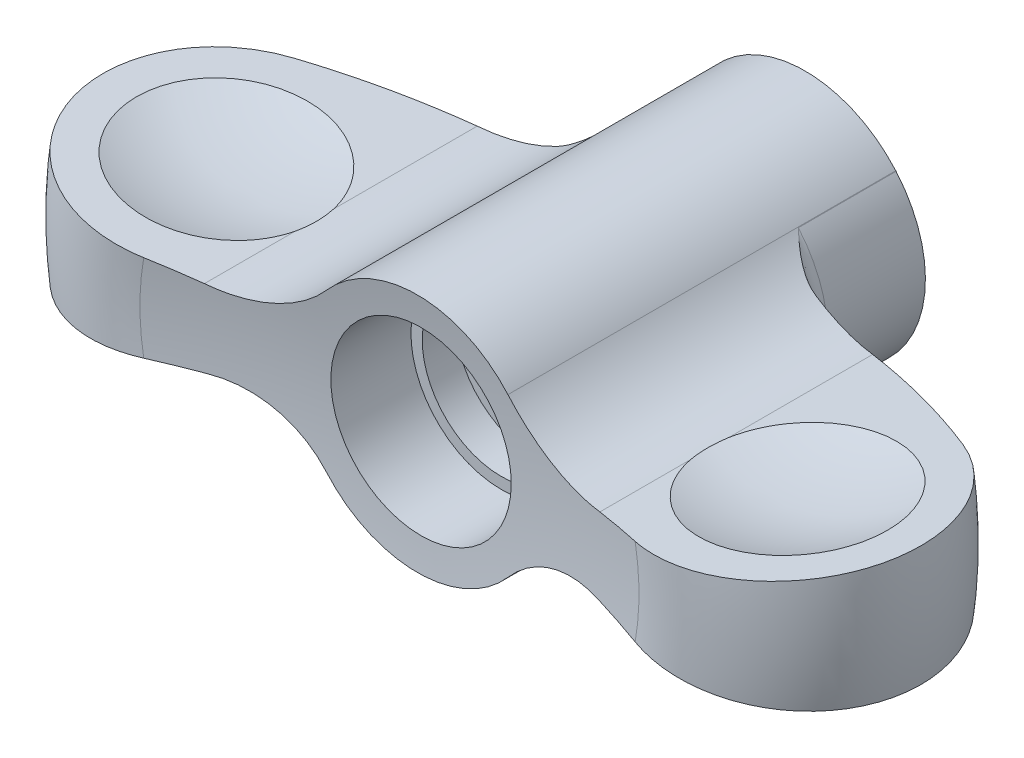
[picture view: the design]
ISO-10303-21;
HEADER;
FILE_DESCRIPTION(('STEP AP214'),'2;1');
FILE_NAME('part.step','',(''),(''),'','','');
FILE_SCHEMA(('AUTOMOTIVE_DESIGN { 1 0 10303 214 1 1 1 1 }'));
ENDSEC;
DATA;
#1=APPLICATION_CONTEXT('core data for automotive mechanical design processes');
#2=APPLICATION_PROTOCOL_DEFINITION('international standard','automotive_design',2000,#1);
#3=PRODUCT_CONTEXT('',#1,'mechanical');
#4=PRODUCT('Part','Part','',(#3));
#5=PRODUCT_RELATED_PRODUCT_CATEGORY('part','',(#4));
#6=PRODUCT_DEFINITION_FORMATION('','',#4);
#7=PRODUCT_DEFINITION_CONTEXT('part definition',#1,'design');
#8=PRODUCT_DEFINITION('design','',#6,#7);
#9=PRODUCT_DEFINITION_SHAPE('','',#8);
#10=(LENGTH_UNIT() NAMED_UNIT(*) SI_UNIT(.MILLI.,.METRE.));
#11=(NAMED_UNIT(*) PLANE_ANGLE_UNIT() SI_UNIT($,.RADIAN.));
#12=(NAMED_UNIT(*) SI_UNIT($,.STERADIAN.) SOLID_ANGLE_UNIT());
#13=UNCERTAINTY_MEASURE_WITH_UNIT(LENGTH_MEASURE(1.E-05),#10,'distance_accuracy_value','');
#14=(GEOMETRIC_REPRESENTATION_CONTEXT(3) GLOBAL_UNCERTAINTY_ASSIGNED_CONTEXT((#13)) GLOBAL_UNIT_ASSIGNED_CONTEXT((#10,
#11,#12)) REPRESENTATION_CONTEXT('',''));
#15=CARTESIAN_POINT('',(0.,0.,0.));
#16=DIRECTION('',(0.,0.,1.));
#17=DIRECTION('',(1.,0.,0.));
#18=AXIS2_PLACEMENT_3D('',#15,#16,#17);
#19=CARTESIAN_POINT('',(0.,0.,6.5));
#20=DIRECTION('',(0.,0.,1.));
#21=DIRECTION('',(0.,-1.,0.));
#22=AXIS2_PLACEMENT_3D('',#19,#20,#21);
#23=TOROIDAL_SURFACE('',#22,9.4,1.40000000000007);
#24=DIRECTION('',(0.,0.,1.));
#25=VECTOR('',#24,1.);
#26=CARTESIAN_POINT('',(6.03890778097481,-5.2470556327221,-7.0380739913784));
#27=LINE('',#26,#25);
#28=CARTESIAN_POINT('',(6.03890778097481,-5.2470556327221,6.5));
#29=VERTEX_POINT('',#28);
#30=CARTESIAN_POINT('',(6.03890778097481,-5.2470556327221,6.50212008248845));
#31=VERTEX_POINT('',#30);
#32=EDGE_CURVE('E180',#29,#31,#27,.T.);
#33=ORIENTED_EDGE('',*,*,#32,.F.);
#34=CARTESIAN_POINT('',(0.,0.,6.5));
#35=DIRECTION('',(0.,0.,1.));
#36=DIRECTION('',(0.,-1.,0.));
#37=AXIS2_PLACEMENT_3D('',#34,#35,#36);
#38=CIRCLE('',#37,8.);
#39=CARTESIAN_POINT('',(6.0470062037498,5.23772049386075,6.5));
#40=VERTEX_POINT('',#39);
#41=EDGE_CURVE('E402',#29,#40,#38,.T.);
#42=ORIENTED_EDGE('',*,*,#41,.T.);
#43=CARTESIAN_POINT('',(8.59898254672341,3.29412567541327,7.8868206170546));
#44=CARTESIAN_POINT('',(8.51141815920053,3.33631021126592,7.87757295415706));
#45=CARTESIAN_POINT('',(8.42512324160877,3.37986689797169,7.86383925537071));
#46=CARTESIAN_POINT('',(8.25552733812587,3.46930142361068,7.82879311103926));
#47=CARTESIAN_POINT('',(8.17222071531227,3.51517445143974,7.80749586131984));
#48=CARTESIAN_POINT('',(8.00928400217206,3.60865711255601,7.75884124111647));
#49=CARTESIAN_POINT('',(7.92963203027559,3.65625212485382,7.73152791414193));
#50=CARTESIAN_POINT('',(7.77338079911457,3.75327693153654,7.67180748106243));
#51=CARTESIAN_POINT('',(7.69678296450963,3.80270756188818,7.63939803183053));
#52=CARTESIAN_POINT('',(7.51724415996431,3.9228836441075,7.55691032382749));
#53=CARTESIAN_POINT('',(7.41571994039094,3.99440279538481,7.50487985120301));
#54=CARTESIAN_POINT('',(7.21816387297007,4.14040328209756,7.39471306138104));
#55=CARTESIAN_POINT('',(7.12213718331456,4.21488729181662,7.3365711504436));
#56=CARTESIAN_POINT('',(6.89909833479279,4.39600037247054,7.19247655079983));
#57=CARTESIAN_POINT('',(6.77446584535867,4.50392052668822,7.10446467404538));
#58=CARTESIAN_POINT('',(6.57485157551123,4.68763024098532,6.9540735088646));
#59=CARTESIAN_POINT('',(6.49736321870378,4.7619072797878,6.89312126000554));
#60=CARTESIAN_POINT('',(6.37296054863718,4.88601102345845,6.79178977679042));
#61=CARTESIAN_POINT('',(6.32499252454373,4.93511681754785,6.75182074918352));
#62=CARTESIAN_POINT('',(6.24779625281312,5.01619850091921,6.68620361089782));
#63=CARTESIAN_POINT('',(6.21813895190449,5.04786120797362,6.66067187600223));
#64=CARTESIAN_POINT('',(6.17033482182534,5.09973563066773,6.61900123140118));
#65=CARTESIAN_POINT('',(6.15201397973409,5.11982116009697,6.60290481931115));
#66=CARTESIAN_POINT('',(6.12244478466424,5.15257170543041,6.57667362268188));
#67=CARTESIAN_POINT('',(6.11112210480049,5.16519318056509,6.56656814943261));
#68=CARTESIAN_POINT('',(6.09283224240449,5.18571154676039,6.55006512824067));
#69=CARTESIAN_POINT('',(6.08582724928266,5.19360153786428,6.54370123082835));
#70=CARTESIAN_POINT('',(6.07451533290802,5.2063931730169,6.53324372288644));
#71=CARTESIAN_POINT('',(6.07018138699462,5.21130628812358,6.52919336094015));
#72=CARTESIAN_POINT('',(6.06319526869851,5.21924541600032,6.52245610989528));
#73=CARTESIAN_POINT('',(6.06051754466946,5.22229316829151,6.51982285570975));
#74=CARTESIAN_POINT('',(6.05622209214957,5.22718951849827,6.51535418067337));
#75=CARTESIAN_POINT('',(6.05457550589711,5.22906827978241,6.51357999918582));
#76=CARTESIAN_POINT('',(6.05195439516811,5.23206168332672,6.51048008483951));
#77=CARTESIAN_POINT('',(6.05094876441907,5.23321085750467,6.50921868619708));
#78=CARTESIAN_POINT('',(6.04953567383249,5.23482648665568,6.50715333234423));
#79=CARTESIAN_POINT('',(6.04907752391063,5.2353504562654,6.50643002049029));
#80=CARTESIAN_POINT('',(6.04823578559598,5.2363133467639,6.50488896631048));
#81=CARTESIAN_POINT('',(6.04785159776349,5.2367529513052,6.50407207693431));
#82=CARTESIAN_POINT('',(6.04743690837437,5.23722752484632,6.50283591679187));
#83=CARTESIAN_POINT('',(6.04733310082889,5.23734633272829,6.50247536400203));
#84=CARTESIAN_POINT('',(6.04716429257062,5.23753954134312,6.50173449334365));
#85=CARTESIAN_POINT('',(6.04709913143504,5.23761412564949,6.50135426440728));
#86=CARTESIAN_POINT('',(6.04703741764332,5.23768476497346,6.50077580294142));
#87=CARTESIAN_POINT('',(6.04702284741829,5.23770144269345,6.50058184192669));
#88=CARTESIAN_POINT('',(6.04700611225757,5.23772059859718,6.50019185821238));
#89=CARTESIAN_POINT('',(6.04700400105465,5.23772301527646,6.49999583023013));
#90=CARTESIAN_POINT('',(6.0470084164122,5.23771796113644,6.4997999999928));
#91=B_SPLINE_CURVE_WITH_KNOTS('',3,(#43,#44,#45,#46,#47,#48,#49,#50,#51,#52,#53,#54,#55,#56,#57,
#58,#59,#60,#61,#62,#63,#64,#65,#66,#67,#68,#69,#70,#71,#72,#73,#74,#75,#76,#77,#78,#79,#80,#81,
#82,#83,#84,#85,#86,#87,#88,#89,#90),.UNSPECIFIED.,.F.,.F.,(4,2,2,2,2,2,2,2,2,2,2,2,2,2,2,2,2,2,
2,2,2,2,2,4),(0.,0.292609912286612,0.58463524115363,0.874589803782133,1.16467807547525,
1.56824756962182,1.97218971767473,2.53235699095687,2.9025934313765,3.14087410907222,
3.29188442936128,3.38666478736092,3.44588137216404,3.48284532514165,3.50595247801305,
3.52045898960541,3.52964962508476,3.53557823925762,3.53858720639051,3.54157065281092,
3.54274772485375,3.54391987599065,3.54450469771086,3.54509203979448),.UNSPECIFIED.);
#92=CARTESIAN_POINT('',(8.59708881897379,3.29503849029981,7.8866206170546));
#93=VERTEX_POINT('',#92);
#94=EDGE_CURVE('E347',#93,#40,#91,.T.);
#95=ORIENTED_EDGE('',*,*,#94,.F.);
#96=CARTESIAN_POINT('',(0.,0.,7.8866206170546));
#97=DIRECTION('',(0.,0.,1.));
#98=DIRECTION('',(0.,-1.,0.));
#99=AXIS2_PLACEMENT_3D('',#96,#97,#98);
#100=CIRCLE('',#99,9.20691125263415);
#101=CARTESIAN_POINT('',(8.59734587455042,-3.29436772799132,7.8866206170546));
#102=VERTEX_POINT('',#101);
#103=EDGE_CURVE('E398',#102,#93,#100,.T.);
#104=ORIENTED_EDGE('',*,*,#103,.F.);
#105=CARTESIAN_POINT('',(9.24838774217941,-3.01522896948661,7.8611549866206));
#106=CARTESIAN_POINT('',(9.19367387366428,-3.03586597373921,7.87212843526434));
#107=CARTESIAN_POINT('',(9.13880326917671,-3.05725699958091,7.88061358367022));
#108=CARTESIAN_POINT('',(9.02918340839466,-3.10140121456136,7.89300588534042));
#109=CARTESIAN_POINT('',(8.97443409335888,-3.12415231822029,7.8969198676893));
#110=CARTESIAN_POINT('',(8.81189994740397,-3.19383993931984,7.90240025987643));
#111=CARTESIAN_POINT('',(8.70468460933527,-3.24264189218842,7.8979138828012));
#112=CARTESIAN_POINT('',(8.51244986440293,-3.33527790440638,7.87768998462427));
#113=CARTESIAN_POINT('',(8.42685948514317,-3.37846333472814,7.86408345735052));
#114=CARTESIAN_POINT('',(8.25844994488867,-3.46721413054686,7.82939829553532));
#115=CARTESIAN_POINT('',(8.1756320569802,-3.51278056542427,7.80831627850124));
#116=CARTESIAN_POINT('',(7.93073591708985,-3.65314361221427,7.73552099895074));
#117=CARTESIAN_POINT('',(7.77324575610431,-3.75110326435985,7.67439750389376));
#118=CARTESIAN_POINT('',(7.51464053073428,-3.92422259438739,7.55555975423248));
#119=CARTESIAN_POINT('',(7.41040744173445,-3.99776965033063,7.50198430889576));
#120=CARTESIAN_POINT('',(7.20775000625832,-4.14796966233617,7.38844495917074));
#121=CARTESIAN_POINT('',(7.10932762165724,-4.2246236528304,7.32847891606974));
#122=CARTESIAN_POINT('',(6.91810375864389,-4.3807228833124,7.20404785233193));
#123=CARTESIAN_POINT('',(6.82529242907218,-4.46016282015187,7.13959117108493));
#124=CARTESIAN_POINT('',(6.64465512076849,-4.62196874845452,7.0075093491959));
#125=CARTESIAN_POINT('',(6.55682825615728,-4.70433421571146,6.93988477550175));
#126=CARTESIAN_POINT('',(6.43396887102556,-4.82482237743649,6.84137296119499));
#127=CARTESIAN_POINT('',(6.3970838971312,-4.86171240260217,6.81126516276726));
#128=CARTESIAN_POINT('',(6.32415661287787,-4.93608562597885,6.75076275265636));
#129=CARTESIAN_POINT('',(6.28811428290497,-4.97356881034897,6.72036814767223));
#130=CARTESIAN_POINT('',(6.23466025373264,-5.03025441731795,6.67467473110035));
#131=CARTESIAN_POINT('',(6.21694916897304,-5.04922052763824,6.65943137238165));
#132=CARTESIAN_POINT('',(6.18174487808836,-5.08728721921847,6.62885737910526));
#133=CARTESIAN_POINT('',(6.16425168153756,-5.10638780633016,6.61352674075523));
#134=CARTESIAN_POINT('',(6.12939253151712,-5.14482758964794,6.58303704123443));
#135=CARTESIAN_POINT('',(6.11202655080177,-5.16416673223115,6.56787794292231));
#136=CARTESIAN_POINT('',(6.07777325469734,-5.20267654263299,6.53681590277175));
#137=CARTESIAN_POINT('',(6.06088576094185,-5.22184727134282,6.52091324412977));
#138=CARTESIAN_POINT('',(6.04125231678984,-5.24436288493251,6.50407143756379));
#139=CARTESIAN_POINT('',(6.03883130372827,-5.24714315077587,6.50202251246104));
#140=CARTESIAN_POINT('',(6.036402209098,-5.24993655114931,6.5));
#141=B_SPLINE_CURVE_WITH_KNOTS('',3,(#105,#106,#107,#108,#109,#110,#111,#112,#113,#114,#115,
#116,#117,#118,#119,#120,#121,#122,#123,#124,#125,#126,#127,#128,#129,#130,#131,#132,#133,#134,
#135,#136,#137,#138,#139,#140),.UNSPECIFIED.,.F.,.F.,(4,2,2,2,2,2,2,2,2,2,2,2,2,2,2,2,2,4),(0.,
0.178348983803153,0.356431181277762,0.708912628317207,0.999032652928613,1.28928411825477,
1.87321137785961,2.28803676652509,2.70300142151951,3.1172150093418,3.53135474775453,
3.71204340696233,3.89272785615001,3.98301462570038,4.07330534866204,4.16357613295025,
4.25381281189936,4.26646608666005),.UNSPECIFIED.);
#142=EDGE_CURVE('E331',#31,#102,#141,.F.);
#143=ORIENTED_EDGE('',*,*,#142,.F.);
#144=EDGE_LOOP('',(#33,#42,#95,#104,#143));
#145=FACE_BOUND('',#144,.T.);
#146=ADVANCED_FACE('F14',(#145),#23,.F.);
#147=CARTESIAN_POINT('',(0.,0.,84.9218512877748));
#148=DIRECTION('',(0.,0.,1.));
#149=DIRECTION('',(0.,-1.,0.));
#150=AXIS2_PLACEMENT_3D('',#147,#148,#149);
#151=DEGENERATE_TOROIDAL_SURFACE('',#150,0.267106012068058,59.7,.F.);
#152=CARTESIAN_POINT('',(0.,0.,25.5517124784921));
#153=DIRECTION('',(0.,0.,1.));
#154=DIRECTION('',(0.,-1.,0.));
#155=AXIS2_PLACEMENT_3D('',#152,#153,#154);
#156=CIRCLE('',#155,6.);
#157=CARTESIAN_POINT('',(0.,-6.,25.5517124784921));
#158=VERTEX_POINT('',#157);
#159=EDGE_CURVE('E226',#158,#158,#156,.T.);
#160=ORIENTED_EDGE('',*,*,#159,.F.);
#161=EDGE_LOOP('',(#160));
#162=FACE_BOUND('',#161,.T.);
#163=CARTESIAN_POINT('',(12.9966083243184,-2.55402529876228,26.7711157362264));
#164=CARTESIAN_POINT('',(12.7754529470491,-2.52825709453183,26.719533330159));
#165=CARTESIAN_POINT('',(12.5528725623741,-2.5117272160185,26.6693936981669));
#166=CARTESIAN_POINT('',(12.1063783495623,-2.49733345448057,26.5723334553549));
#167=CARTESIAN_POINT('',(11.8824643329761,-2.49947227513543,26.5254133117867));
#168=CARTESIAN_POINT('',(11.4348095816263,-2.52261669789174,26.4351255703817));
#169=CARTESIAN_POINT('',(11.2110689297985,-2.54362860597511,26.3917591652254));
#170=CARTESIAN_POINT('',(10.7654590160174,-2.60455176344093,26.3089232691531));
#171=CARTESIAN_POINT('',(10.5435896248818,-2.64446169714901,26.2694535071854));
#172=CARTESIAN_POINT('',(10.1029278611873,-2.7431637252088,26.1946447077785));
#173=CARTESIAN_POINT('',(9.88414203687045,-2.80199107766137,26.1593135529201));
#174=CARTESIAN_POINT('',(9.45174044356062,-2.93823754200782,26.0931563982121));
#175=CARTESIAN_POINT('',(9.23812452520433,-3.01565611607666,26.0623302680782));
#176=CARTESIAN_POINT('',(8.81794496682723,-3.18856082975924,26.0054747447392));
#177=CARTESIAN_POINT('',(8.61137399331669,-3.28402745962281,25.979440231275));
#178=CARTESIAN_POINT('',(8.20669244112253,-3.49247951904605,25.9323600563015));
#179=CARTESIAN_POINT('',(8.00858079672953,-3.60546273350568,25.9113137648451));
#180=CARTESIAN_POINT('',(7.65039872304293,-3.83057518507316,25.8770779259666));
#181=CARTESIAN_POINT('',(7.48897596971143,-3.94045548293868,25.8631917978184));
#182=CARTESIAN_POINT('',(7.1744293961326,-4.17187167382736,25.8393036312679));
#183=CARTESIAN_POINT('',(7.02130457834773,-4.29340616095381,25.8293011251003));
#184=CARTESIAN_POINT('',(6.72399395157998,-4.54769946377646,25.8132388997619));
#185=CARTESIAN_POINT('',(6.57982418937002,-4.68047747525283,25.8071860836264));
#186=CARTESIAN_POINT('',(6.30152732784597,-4.95633540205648,25.7990887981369));
#187=CARTESIAN_POINT('',(6.16740216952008,-5.09941729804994,25.7970451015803));
#188=CARTESIAN_POINT('',(6.03873367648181,-5.2472556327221,25.7970260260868));
#189=B_SPLINE_CURVE_WITH_KNOTS('',3,(#163,#164,#165,#166,#167,#168,#169,#170,#171,#172,#173,
#174,#175,#176,#177,#178,#179,#180,#181,#182,#183,#184,#185,#186,#187,#188),.UNSPECIFIED.,.F.,
.F.,(4,2,2,2,2,2,2,2,2,2,2,2,4),(0.,0.685469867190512,1.37103900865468,2.05683730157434,
2.74258785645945,3.42962398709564,4.1166402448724,4.80291804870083,5.48910913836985,
6.07586072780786,6.66254162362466,7.25024515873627,7.83806196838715),.UNSPECIFIED.);
#190=CARTESIAN_POINT('',(12.9964083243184,-2.55400201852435,26.7710690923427));
#191=VERTEX_POINT('',#190);
#192=CARTESIAN_POINT('',(6.03890778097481,-5.2470556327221,25.7970260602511));
#193=VERTEX_POINT('',#192);
#194=EDGE_CURVE('E337',#191,#193,#189,.T.);
#195=ORIENTED_EDGE('',*,*,#194,.F.);
#196=CARTESIAN_POINT('',(12.9962083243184,-2.55398166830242,26.7710225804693));
#197=CARTESIAN_POINT('',(13.5586098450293,-2.61120664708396,26.9018172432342));
#198=CARTESIAN_POINT('',(14.1188767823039,-2.66821442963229,27.0407918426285));
#199=CARTESIAN_POINT('',(15.2351414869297,-2.78179560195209,27.3351009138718));
#200=CARTESIAN_POINT('',(15.7911392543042,-2.83836899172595,27.4904353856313));
#201=CARTESIAN_POINT('',(16.3450024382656,-2.89472518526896,27.6539497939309));
#202=B_SPLINE_CURVE_WITH_KNOTS('',3,(#196,#197,#198,#199,#200,#201),.UNSPECIFIED.,.F.,.F.,(4,2,
4),(0.,1.74016258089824,3.48032515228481),.UNSPECIFIED.);
#203=CARTESIAN_POINT('',(16.3443249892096,-2.89465625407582,27.6537497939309));
#204=VERTEX_POINT('',#203);
#205=EDGE_CURVE('E277',#191,#204,#202,.T.);
#206=ORIENTED_EDGE('',*,*,#205,.T.);
#207=CARTESIAN_POINT('',(0.,0.,27.6537497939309));
#208=DIRECTION('',(0.,0.,1.));
#209=DIRECTION('',(0.,-1.,0.));
#210=AXIS2_PLACEMENT_3D('',#207,#208,#209);
#211=CIRCLE('',#210,16.5986744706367);
#212=CARTESIAN_POINT('',(16.3437132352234,2.89810832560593,27.6537497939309));
#213=VERTEX_POINT('',#212);
#214=EDGE_CURVE('E390',#204,#213,#211,.T.);
#215=ORIENTED_EDGE('',*,*,#214,.T.);
#216=CARTESIAN_POINT('',(13.1526156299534,2.57444288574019,26.8078255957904));
#217=CARTESIAN_POINT('',(13.6884788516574,2.6287942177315,26.9339805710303));
#218=CARTESIAN_POINT('',(14.2223917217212,2.68294773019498,27.0675684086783));
#219=CARTESIAN_POINT('',(15.2863167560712,2.79085911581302,27.3496098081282));
#220=CARTESIAN_POINT('',(15.8163289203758,2.84461698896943,27.4980633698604));
#221=CARTESIAN_POINT('',(16.3443907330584,2.89817704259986,27.6539497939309));
#222=B_SPLINE_CURVE_WITH_KNOTS('',3,(#216,#217,#218,#219,#220,#221),.UNSPECIFIED.,.F.,.F.,(4,2,
4),(0.,1.65908751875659,3.31817502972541),.UNSPECIFIED.);
#223=CARTESIAN_POINT('',(13.1528156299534,2.57446317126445,26.8078726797));
#224=VERTEX_POINT('',#223);
#225=EDGE_CURVE('E296',#224,#213,#222,.T.);
#226=ORIENTED_EDGE('',*,*,#225,.F.);
#227=CARTESIAN_POINT('',(6.024532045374,5.26355694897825,25.7970262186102));
#228=CARTESIAN_POINT('',(6.16690476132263,5.09913304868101,25.7968869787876));
#229=CARTESIAN_POINT('',(6.31601972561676,4.94055485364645,25.7992439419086));
#230=CARTESIAN_POINT('',(6.62655584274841,4.63614521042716,25.8088925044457));
#231=CARTESIAN_POINT('',(6.7879754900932,4.49031220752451,25.8161835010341));
#232=CARTESIAN_POINT('',(7.12145474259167,4.21284299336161,25.8356118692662));
#233=CARTESIAN_POINT('',(7.29347942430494,4.08116373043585,25.847733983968));
#234=CARTESIAN_POINT('',(7.64736462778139,3.83234945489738,25.8767149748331));
#235=CARTESIAN_POINT('',(7.82922517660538,3.71521448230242,25.893573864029));
#236=CARTESIAN_POINT('',(8.20178776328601,3.49604471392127,25.9319185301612));
#237=CARTESIAN_POINT('',(8.39250457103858,3.39403642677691,25.9534122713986));
#238=CARTESIAN_POINT('',(8.78119845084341,3.20593098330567,26.0008427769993));
#239=CARTESIAN_POINT('',(8.97917867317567,3.11984083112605,26.0267814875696));
#240=CARTESIAN_POINT('',(9.38110362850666,2.96402714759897,26.0829169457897));
#241=CARTESIAN_POINT('',(9.58505370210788,2.89431880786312,26.1131176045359));
#242=CARTESIAN_POINT('',(9.99723627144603,2.77173272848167,26.1775161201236));
#243=CARTESIAN_POINT('',(10.2054670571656,2.71884840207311,26.2117124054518));
#244=CARTESIAN_POINT('',(10.641032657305,2.62666034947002,26.286643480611));
#245=CARTESIAN_POINT('',(10.8686042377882,2.58871528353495,26.3276789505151));
#246=CARTESIAN_POINT('',(11.325443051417,2.5326356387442,26.4137825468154));
#247=CARTESIAN_POINT('',(11.5547105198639,2.51450386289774,26.4588512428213));
#248=CARTESIAN_POINT('',(12.0133084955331,2.49800092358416,26.552689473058));
#249=CARTESIAN_POINT('',(12.242638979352,2.49963935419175,26.6014607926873));
#250=CARTESIAN_POINT('',(12.6995448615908,2.5224660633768,26.7023049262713));
#251=CARTESIAN_POINT('',(12.927120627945,2.54365012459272,26.7543770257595));
#252=CARTESIAN_POINT('',(13.1530156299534,2.5744904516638,26.8079200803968));
#253=B_SPLINE_CURVE_WITH_KNOTS('',3,(#227,#228,#229,#230,#231,#232,#233,#234,#235,#236,#237,
#238,#239,#240,#241,#242,#243,#244,#245,#246,#247,#248,#249,#250,#251,#252),.UNSPECIFIED.,.F.,
.F.,(4,2,2,2,2,2,2,2,2,2,2,2,4),(0.,0.65228767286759,1.3044956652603,1.95466006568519,
2.60482625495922,3.25611868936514,3.90769702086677,4.55987722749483,5.21180178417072,
5.91390661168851,6.61611075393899,7.31865567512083,8.02104904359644),.UNSPECIFIED.);
#254=CARTESIAN_POINT('',(6.02470527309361,5.26335694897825,25.7970260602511));
#255=VERTEX_POINT('',#254);
#256=EDGE_CURVE('E375',#255,#224,#253,.T.);
#257=ORIENTED_EDGE('',*,*,#256,.F.);
#258=CARTESIAN_POINT('',(0.,0.,25.7970260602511));
#259=DIRECTION('',(0.,0.,1.));
#260=DIRECTION('',(0.,-1.,0.));
#261=AXIS2_PLACEMENT_3D('',#258,#259,#260);
#262=CIRCLE('',#261,8.);
#263=CARTESIAN_POINT('',(-6.0247052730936,5.26335694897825,25.7970260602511));
#264=VERTEX_POINT('',#263);
#265=EDGE_CURVE('E382',#255,#264,#262,.T.);
#266=ORIENTED_EDGE('',*,*,#265,.T.);
#267=CARTESIAN_POINT('',(-6.02453204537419,5.26355694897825,25.7970262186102));
#268=CARTESIAN_POINT('',(-6.16690476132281,5.099133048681,25.7968869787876));
#269=CARTESIAN_POINT('',(-6.31601972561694,4.94055485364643,25.7992439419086));
#270=CARTESIAN_POINT('',(-6.62655584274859,4.63614521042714,25.8088925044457));
#271=CARTESIAN_POINT('',(-6.78797549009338,4.4903122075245,25.8161835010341));
#272=CARTESIAN_POINT('',(-7.12145474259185,4.21284299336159,25.8356118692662));
#273=CARTESIAN_POINT('',(-7.29347942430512,4.08116373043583,25.847733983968));
#274=CARTESIAN_POINT('',(-7.64736462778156,3.83234945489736,25.8767149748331));
#275=CARTESIAN_POINT('',(-7.82922517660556,3.71521448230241,25.893573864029));
#276=CARTESIAN_POINT('',(-8.20178776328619,3.49604471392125,25.9319185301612));
#277=CARTESIAN_POINT('',(-8.39250457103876,3.39403642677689,25.9534122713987));
#278=CARTESIAN_POINT('',(-8.78119845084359,3.20593098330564,26.0008427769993));
#279=CARTESIAN_POINT('',(-8.97917867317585,3.11984083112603,26.0267814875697));
#280=CARTESIAN_POINT('',(-9.38110362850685,2.96402714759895,26.0829169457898));
#281=CARTESIAN_POINT('',(-9.58505370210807,2.89431880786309,26.1131176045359));
#282=CARTESIAN_POINT('',(-9.99723627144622,2.77173272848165,26.1775161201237));
#283=CARTESIAN_POINT('',(-10.2054670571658,2.7188484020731,26.2117124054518));
#284=CARTESIAN_POINT('',(-10.6410326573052,2.62666034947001,26.286643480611));
#285=CARTESIAN_POINT('',(-10.8686042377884,2.58871528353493,26.3276789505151));
#286=CARTESIAN_POINT('',(-11.3254430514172,2.53263563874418,26.4137825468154));
#287=CARTESIAN_POINT('',(-11.5547105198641,2.51450386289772,26.4588512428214));
#288=CARTESIAN_POINT('',(-12.0133084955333,2.49800092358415,26.5526894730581));
#289=CARTESIAN_POINT('',(-12.2426389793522,2.49963935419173,26.6014607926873));
#290=CARTESIAN_POINT('',(-12.699544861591,2.52246606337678,26.7023049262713));
#291=CARTESIAN_POINT('',(-12.9271206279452,2.5436501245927,26.7543770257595));
#292=CARTESIAN_POINT('',(-13.1530156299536,2.57449045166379,26.8079200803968));
#293=B_SPLINE_CURVE_WITH_KNOTS('',3,(#267,#268,#269,#270,#271,#272,#273,#274,#275,#276,#277,
#278,#279,#280,#281,#282,#283,#284,#285,#286,#287,#288,#289,#290,#291,#292),.UNSPECIFIED.,.F.,
.F.,(4,2,2,2,2,2,2,2,2,2,2,2,4),(0.,0.652287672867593,1.3044956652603,1.95466006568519,
2.60482625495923,3.25611868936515,3.90769702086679,4.55987722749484,5.21180178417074,
5.91390661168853,6.61611075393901,7.31865567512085,8.02104904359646),.UNSPECIFIED.);
#294=CARTESIAN_POINT('',(-13.1528156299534,2.57446317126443,26.8078726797));
#295=VERTEX_POINT('',#294);
#296=EDGE_CURVE('E497',#264,#295,#293,.T.);
#297=ORIENTED_EDGE('',*,*,#296,.T.);
#298=CARTESIAN_POINT('',(-13.1526156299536,2.57444288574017,26.8078255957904));
#299=CARTESIAN_POINT('',(-13.6884788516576,2.62879421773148,26.9339805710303));
#300=CARTESIAN_POINT('',(-14.2223917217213,2.68294773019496,27.0675684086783));
#301=CARTESIAN_POINT('',(-15.2863167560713,2.79085911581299,27.3496098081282));
#302=CARTESIAN_POINT('',(-15.8163289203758,2.8446169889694,27.4980633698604));
#303=CARTESIAN_POINT('',(-16.3443907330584,2.89817704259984,27.6539497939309));
#304=B_SPLINE_CURVE_WITH_KNOTS('',3,(#298,#299,#300,#301,#302,#303),.UNSPECIFIED.,.F.,.F.,(4,2,
4),(0.,1.6590875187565,3.31817502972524),.UNSPECIFIED.);
#305=CARTESIAN_POINT('',(-16.3437132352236,2.89810832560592,27.6537497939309));
#306=VERTEX_POINT('',#305);
#307=EDGE_CURVE('E196',#295,#306,#304,.T.);
#308=ORIENTED_EDGE('',*,*,#307,.T.);
#309=CARTESIAN_POINT('',(-16.3443249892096,-2.89465625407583,27.6537497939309));
#310=VERTEX_POINT('',#309);
#311=EDGE_CURVE('E389',#306,#310,#211,.T.);
#312=ORIENTED_EDGE('',*,*,#311,.T.);
#313=CARTESIAN_POINT('',(-12.9962083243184,-2.55398166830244,26.7710225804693));
#314=CARTESIAN_POINT('',(-13.5586098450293,-2.61120664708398,26.9018172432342));
#315=CARTESIAN_POINT('',(-14.1188767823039,-2.6682144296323,27.0407918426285));
#316=CARTESIAN_POINT('',(-15.2351414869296,-2.7817956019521,27.3351009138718));
#317=CARTESIAN_POINT('',(-15.7911392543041,-2.83836899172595,27.4904353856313));
#318=CARTESIAN_POINT('',(-16.3450024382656,-2.89472518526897,27.6539497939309));
#319=B_SPLINE_CURVE_WITH_KNOTS('',3,(#313,#314,#315,#316,#317,#318),.UNSPECIFIED.,.F.,.F.,(4,2,
4),(0.,1.74016258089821,3.48032515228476),.UNSPECIFIED.);
#320=CARTESIAN_POINT('',(-12.9964083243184,-2.55400201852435,26.77106909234));
#321=VERTEX_POINT('',#320);
#322=EDGE_CURVE('E278',#321,#310,#319,.T.);
#323=ORIENTED_EDGE('',*,*,#322,.F.);
#324=CARTESIAN_POINT('',(-12.9966083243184,-2.55402529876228,26.7711157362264));
#325=CARTESIAN_POINT('',(-12.7754529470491,-2.52825709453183,26.719533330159));
#326=CARTESIAN_POINT('',(-12.5528725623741,-2.5117272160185,26.6693936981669));
#327=CARTESIAN_POINT('',(-12.1063783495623,-2.49733345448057,26.5723334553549));
#328=CARTESIAN_POINT('',(-11.8824643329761,-2.49947227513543,26.5254133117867));
#329=CARTESIAN_POINT('',(-11.4348095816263,-2.52261669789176,26.4351255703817));
#330=CARTESIAN_POINT('',(-11.2110689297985,-2.54362860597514,26.3917591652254));
#331=CARTESIAN_POINT('',(-10.7654590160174,-2.60455176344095,26.3089232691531));
#332=CARTESIAN_POINT('',(-10.5435896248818,-2.64446169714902,26.2694535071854));
#333=CARTESIAN_POINT('',(-10.1029278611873,-2.74316372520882,26.1946447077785));
#334=CARTESIAN_POINT('',(-9.88414203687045,-2.80199107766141,26.1593135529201));
#335=CARTESIAN_POINT('',(-9.45174044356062,-2.93823754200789,26.0931563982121));
#336=CARTESIAN_POINT('',(-9.23812452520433,-3.01565611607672,26.0623302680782));
#337=CARTESIAN_POINT('',(-8.81794496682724,-3.18856082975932,26.0054747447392));
#338=CARTESIAN_POINT('',(-8.61137399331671,-3.28402745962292,25.979440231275));
#339=CARTESIAN_POINT('',(-8.20669244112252,-3.49247951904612,25.9323600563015));
#340=CARTESIAN_POINT('',(-8.0085807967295,-3.6054627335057,25.9113137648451));
#341=CARTESIAN_POINT('',(-7.65039872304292,-3.83057518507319,25.8770779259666));
#342=CARTESIAN_POINT('',(-7.48897596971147,-3.94045548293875,25.8631917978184));
#343=CARTESIAN_POINT('',(-7.1744293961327,-4.17187167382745,25.839303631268));
#344=CARTESIAN_POINT('',(-7.02130457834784,-4.29340616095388,25.8293011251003));
#345=CARTESIAN_POINT('',(-6.72399395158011,-4.5476994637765,25.8132388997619));
#346=CARTESIAN_POINT('',(-6.57982418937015,-4.68047747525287,25.8071860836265));
#347=CARTESIAN_POINT('',(-6.30152732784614,-4.9563354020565,25.799088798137));
#348=CARTESIAN_POINT('',(-6.16740216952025,-5.09941729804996,25.7970451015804));
#349=CARTESIAN_POINT('',(-6.03873367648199,-5.24725563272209,25.7970260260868));
#350=B_SPLINE_CURVE_WITH_KNOTS('',3,(#324,#325,#326,#327,#328,#329,#330,#331,#332,#333,#334,
#335,#336,#337,#338,#339,#340,#341,#342,#343,#344,#345,#346,#347,#348,#349),.UNSPECIFIED.,.F.,
.F.,(4,2,2,2,2,2,2,2,2,2,2,2,4),(0.,0.685469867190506,1.37103900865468,2.05683730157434,
2.74258785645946,3.42962398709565,4.11664024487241,4.80291804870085,5.48910913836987,
6.07586072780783,6.66254162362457,7.25024515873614,7.83806196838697),.UNSPECIFIED.);
#351=CARTESIAN_POINT('',(-6.03890778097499,-5.2470556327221,25.7970260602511));
#352=VERTEX_POINT('',#351);
#353=EDGE_CURVE('E338',#321,#352,#350,.T.);
#354=ORIENTED_EDGE('',*,*,#353,.T.);
#355=CARTESIAN_POINT('',(0.,0.,25.7970260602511));
#356=DIRECTION('',(0.,0.,1.));
#357=DIRECTION('',(0.,-1.,0.));
#358=AXIS2_PLACEMENT_3D('',#355,#356,#357);
#359=CIRCLE('',#358,8.);
#360=EDGE_CURVE('E386',#352,#193,#359,.T.);
#361=ORIENTED_EDGE('',*,*,#360,.T.);
#362=EDGE_LOOP('',(#195,#206,#215,#226,#257,#266,#297,#308,#312,#323,#354,#361));
#363=FACE_BOUND('',#362,.T.);
#364=ADVANCED_FACE('F16',(#162,#363),#151,.T.);
#365=CARTESIAN_POINT('',(7.9999999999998,0.,0.));
#366=DIRECTION('',(0.,0.,-1.));
#367=DIRECTION('',(0.,1.,0.));
#368=AXIS2_PLACEMENT_3D('',#365,#366,#367);
#369=PLANE('',#368);
#370=CARTESIAN_POINT('',(0.,0.,0.));
#371=DIRECTION('',(0.,0.,1.));
#372=DIRECTION('',(0.,-1.,0.));
#373=AXIS2_PLACEMENT_3D('',#370,#371,#372);
#374=CIRCLE('',#373,4.);
#375=CARTESIAN_POINT('',(0.,-4.,0.));
#376=VERTEX_POINT('',#375);
#377=EDGE_CURVE('E409',#376,#376,#374,.T.);
#378=ORIENTED_EDGE('',*,*,#377,.T.);
#379=EDGE_LOOP('',(#378));
#380=FACE_BOUND('',#379,.T.);
#381=CARTESIAN_POINT('',(12.0717114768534,10.5010774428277,0.));
#382=DIRECTION('',(0.,0.,-1.));
#383=DIRECTION('',(0.,1.,0.));
#384=AXIS2_PLACEMENT_3D('',#381,#382,#383);
#385=CIRCLE('',#384,8.);
#386=CARTESIAN_POINT('',(6.0470062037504,5.23772049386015,0.));
#387=VERTEX_POINT('',#386);
#388=CARTESIAN_POINT('',(6.024705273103,5.26335694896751,0.));
#389=VERTEX_POINT('',#388);
#390=EDGE_CURVE('E383',#387,#389,#385,.T.);
#391=ORIENTED_EDGE('',*,*,#390,.F.);
#392=CARTESIAN_POINT('',(0.,0.,0.));
#393=DIRECTION('',(0.,0.,1.));
#394=DIRECTION('',(0.,-1.,0.));
#395=AXIS2_PLACEMENT_3D('',#392,#393,#394);
#396=CIRCLE('',#395,8.);
#397=CARTESIAN_POINT('',(-6.04700620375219,5.23772049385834,0.));
#398=VERTEX_POINT('',#397);
#399=EDGE_CURVE('E406',#398,#387,#396,.T.);
#400=ORIENTED_EDGE('',*,*,#399,.F.);
#401=CARTESIAN_POINT('',(-12.0717114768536,10.5010774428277,0.));
#402=DIRECTION('',(0.,0.,-1.));
#403=DIRECTION('',(0.,1.,0.));
#404=AXIS2_PLACEMENT_3D('',#401,#402,#403);
#405=CIRCLE('',#404,8.);
#406=CARTESIAN_POINT('',(-6.02470527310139,5.26335694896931,0.));
#407=VERTEX_POINT('',#406);
#408=EDGE_CURVE('E509',#398,#407,#405,.F.);
#409=ORIENTED_EDGE('',*,*,#408,.T.);
#410=EDGE_CURVE('E405',#389,#407,#396,.T.);
#411=ORIENTED_EDGE('',*,*,#410,.F.);
#412=EDGE_LOOP('',(#391,#400,#409,#411));
#413=FACE_BOUND('',#412,.T.);
#414=ADVANCED_FACE('F431',(#380,#413),#369,.T.);
#415=CARTESIAN_POINT('',(0.,0.,32.9619260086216));
#416=DIRECTION('',(0.,0.,1.));
#417=DIRECTION('',(0.,-1.,0.));
#418=AXIS2_PLACEMENT_3D('',#415,#416,#417);
#419=CYLINDRICAL_SURFACE('',#418,8.);
#420=DIRECTION('',(0.,0.,1.));
#421=VECTOR('',#420,1.);
#422=CARTESIAN_POINT('',(-6.0247052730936,5.26335694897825,-7.0380739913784));
#423=LINE('',#422,#421);
#424=EDGE_CURVE('E170',#407,#264,#423,.T.);
#425=ORIENTED_EDGE('',*,*,#424,.T.);
#426=ORIENTED_EDGE('',*,*,#265,.F.);
#427=DIRECTION('',(0.,0.,1.));
#428=VECTOR('',#427,1.);
#429=CARTESIAN_POINT('',(6.02470527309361,5.26335694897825,-7.0380739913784));
#430=LINE('',#429,#428);
#431=EDGE_CURVE('E520',#389,#255,#430,.T.);
#432=ORIENTED_EDGE('',*,*,#431,.F.);
#433=ORIENTED_EDGE('',*,*,#410,.T.);
#434=EDGE_LOOP('',(#425,#426,#432,#433));
#435=FACE_BOUND('',#434,.T.);
#436=ADVANCED_FACE('F316',(#435),#419,.T.);
#437=DIRECTION('',(0.,0.,1.));
#438=VECTOR('',#437,1.);
#439=CARTESIAN_POINT('',(-6.04700620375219,5.23772049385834,3.25));
#440=LINE('',#439,#438);
#441=CARTESIAN_POINT('',(-6.04700620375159,5.23772049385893,6.5));
#442=VERTEX_POINT('',#441);
#443=EDGE_CURVE('E309',#398,#442,#440,.T.);
#444=ORIENTED_EDGE('',*,*,#443,.F.);
#445=ORIENTED_EDGE('',*,*,#399,.T.);
#446=DIRECTION('',(0.,0.,1.));
#447=VECTOR('',#446,1.);
#448=CARTESIAN_POINT('',(6.0470062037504,5.23772049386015,3.25));
#449=LINE('',#448,#447);
#450=EDGE_CURVE('E354',#387,#40,#449,.T.);
#451=ORIENTED_EDGE('',*,*,#450,.T.);
#452=ORIENTED_EDGE('',*,*,#41,.F.);
#453=ORIENTED_EDGE('',*,*,#32,.T.);
#454=EDGE_CURVE('E177',#31,#193,#27,.T.);
#455=ORIENTED_EDGE('',*,*,#454,.T.);
#456=ORIENTED_EDGE('',*,*,#360,.F.);
#457=DIRECTION('',(0.,0.,1.));
#458=VECTOR('',#457,1.);
#459=CARTESIAN_POINT('',(-6.03890778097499,-5.2470556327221,-7.0380739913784));
#460=LINE('',#459,#458);
#461=CARTESIAN_POINT('',(-6.03890778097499,-5.2470556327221,6.50212008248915));
#462=VERTEX_POINT('',#461);
#463=EDGE_CURVE('E168',#462,#352,#460,.T.);
#464=ORIENTED_EDGE('',*,*,#463,.F.);
#465=CARTESIAN_POINT('',(-6.03890778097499,-5.2470556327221,6.5));
#466=VERTEX_POINT('',#465);
#467=EDGE_CURVE('E176',#466,#462,#460,.T.);
#468=ORIENTED_EDGE('',*,*,#467,.F.);
#469=EDGE_CURVE('E401',#442,#466,#38,.T.);
#470=ORIENTED_EDGE('',*,*,#469,.F.);
#471=EDGE_LOOP('',(#444,#445,#451,#452,#453,#455,#456,#464,#468,#470));
#472=FACE_BOUND('',#471,.T.);
#473=ADVANCED_FACE('F440',(#472),#419,.T.);
#474=ORIENTED_EDGE('',*,*,#469,.T.);
#475=ORIENTED_EDGE('',*,*,#467,.T.);
#476=CARTESIAN_POINT('',(-9.24838774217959,-3.01522896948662,7.8611549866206));
#477=CARTESIAN_POINT('',(-9.19367387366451,-3.03586597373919,7.87212843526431));
#478=CARTESIAN_POINT('',(-9.13880326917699,-3.05725699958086,7.88061358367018));
#479=CARTESIAN_POINT('',(-9.02918340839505,-3.10140121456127,7.89300588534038));
#480=CARTESIAN_POINT('',(-8.97443409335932,-3.12415231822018,7.89691986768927));
#481=CARTESIAN_POINT('',(-8.8118999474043,-3.19383993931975,7.90240025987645));
#482=CARTESIAN_POINT('',(-8.70468460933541,-3.24264189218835,7.89791388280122));
#483=CARTESIAN_POINT('',(-8.51244986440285,-3.33527790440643,7.87768998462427));
#484=CARTESIAN_POINT('',(-8.42685948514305,-3.37846333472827,7.86408345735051));
#485=CARTESIAN_POINT('',(-8.25844994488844,-3.4672141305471,7.82939829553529));
#486=CARTESIAN_POINT('',(-8.1756320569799,-3.51278056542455,7.80831627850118));
#487=CARTESIAN_POINT('',(-7.93073591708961,-3.65314361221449,7.73552099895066));
#488=CARTESIAN_POINT('',(-7.77324575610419,-3.75110326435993,7.67439750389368));
#489=CARTESIAN_POINT('',(-7.51464053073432,-3.9242225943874,7.55555975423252));
#490=CARTESIAN_POINT('',(-7.41040744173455,-3.99776965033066,7.50198430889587));
#491=CARTESIAN_POINT('',(-7.2077500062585,-4.14796966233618,7.38844495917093));
#492=CARTESIAN_POINT('',(-7.10932762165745,-4.22462365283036,7.32847891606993));
#493=CARTESIAN_POINT('',(-6.91810375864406,-4.38072288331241,7.20404785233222));
#494=CARTESIAN_POINT('',(-6.82529242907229,-4.46016282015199,7.13959117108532));
#495=CARTESIAN_POINT('',(-6.64465512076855,-4.62196874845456,7.00750934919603));
#496=CARTESIAN_POINT('',(-6.55682825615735,-4.70433421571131,6.93988477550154));
#497=CARTESIAN_POINT('',(-6.43396887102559,-4.82482237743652,6.84137296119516));
#498=CARTESIAN_POINT('',(-6.39708389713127,-4.86171240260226,6.81126516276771));
#499=CARTESIAN_POINT('',(-6.32415661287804,-4.93608562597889,6.75076275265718));
#500=CARTESIAN_POINT('',(-6.28811428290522,-4.97356881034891,6.72036814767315));
#501=CARTESIAN_POINT('',(-6.2346602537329,-5.03025441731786,6.67467473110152));
#502=CARTESIAN_POINT('',(-6.21694916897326,-5.04922052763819,6.6594313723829));
#503=CARTESIAN_POINT('',(-6.18174487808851,-5.08728721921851,6.62885737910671));
#504=CARTESIAN_POINT('',(-6.16425168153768,-5.10638780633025,6.61352674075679));
#505=CARTESIAN_POINT('',(-6.129392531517,-5.14482758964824,6.5830370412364));
#506=CARTESIAN_POINT('',(-6.11202655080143,-5.1641667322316,6.56787794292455));
#507=CARTESIAN_POINT('',(-6.07777325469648,-5.2026765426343,6.53681590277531));
#508=CARTESIAN_POINT('',(-6.06088576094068,-5.22184727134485,6.52091324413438));
#509=CARTESIAN_POINT('',(-6.04125231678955,-5.24436288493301,6.5040714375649));
#510=CARTESIAN_POINT('',(-6.03883130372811,-5.24714315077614,6.50202251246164));
#511=CARTESIAN_POINT('',(-6.036402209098,-5.2499365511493,6.5));
#512=B_SPLINE_CURVE_WITH_KNOTS('',3,(#476,#477,#478,#479,#480,#481,#482,#483,#484,#485,#486,
#487,#488,#489,#490,#491,#492,#493,#494,#495,#496,#497,#498,#499,#500,#501,#502,#503,#504,#505,
#506,#507,#508,#509,#510,#511),.UNSPECIFIED.,.F.,.F.,(4,2,2,2,2,2,2,2,2,2,2,2,2,2,2,2,2,4),(0.,
0.178348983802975,0.356431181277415,0.708912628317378,0.999032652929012,1.28928411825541,
1.87321137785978,2.28803676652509,2.70300142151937,3.11721500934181,3.53135474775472,
3.71204340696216,3.89272785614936,3.98301462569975,4.07330534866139,4.16357613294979,
4.25381281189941,4.26646608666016),.UNSPECIFIED.);
#513=CARTESIAN_POINT('',(-8.59734587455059,-3.29436772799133,7.8866206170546));
#514=VERTEX_POINT('',#513);
#515=EDGE_CURVE('E323',#462,#514,#512,.F.);
#516=ORIENTED_EDGE('',*,*,#515,.T.);
#517=CARTESIAN_POINT('',(-8.59708881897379,3.2950384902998,7.8866206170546));
#518=VERTEX_POINT('',#517);
#519=EDGE_CURVE('E397',#518,#514,#100,.T.);
#520=ORIENTED_EDGE('',*,*,#519,.F.);
#521=CARTESIAN_POINT('',(-8.59898254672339,3.29412567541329,7.8868206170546));
#522=CARTESIAN_POINT('',(-8.51141815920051,3.33631021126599,7.87757295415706));
#523=CARTESIAN_POINT('',(-8.42512324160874,3.37986689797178,7.86383925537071));
#524=CARTESIAN_POINT('',(-8.25552733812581,3.46930142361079,7.82879311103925));
#525=CARTESIAN_POINT('',(-8.17222071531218,3.51517445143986,7.80749586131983));
#526=CARTESIAN_POINT('',(-8.00928400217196,3.60865711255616,7.75884124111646));
#527=CARTESIAN_POINT('',(-7.92963203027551,3.656252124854,7.73152791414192));
#528=CARTESIAN_POINT('',(-7.77338079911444,3.75327693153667,7.6718074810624));
#529=CARTESIAN_POINT('',(-7.69678296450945,3.80270756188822,7.63939803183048));
#530=CARTESIAN_POINT('',(-7.51724415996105,3.92288364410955,7.55691032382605));
#531=CARTESIAN_POINT('',(-7.41571994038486,3.99440279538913,7.50487985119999));
#532=CARTESIAN_POINT('',(-7.21816387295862,4.14040328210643,7.3947130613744));
#533=CARTESIAN_POINT('',(-7.12213718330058,4.21488729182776,7.33657115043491));
#534=CARTESIAN_POINT('',(-6.89909833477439,4.39600037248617,7.19247655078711));
#535=CARTESIAN_POINT('',(-6.7744658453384,4.50392052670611,7.10446467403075));
#536=CARTESIAN_POINT('',(-6.57485157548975,4.68763024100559,6.95407350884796));
#537=CARTESIAN_POINT('',(-6.49736321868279,4.7619072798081,6.89312125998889));
#538=CARTESIAN_POINT('',(-6.37296054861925,4.88601102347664,6.79178977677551));
#539=CARTESIAN_POINT('',(-6.32499252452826,4.93511681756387,6.75182074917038));
#540=CARTESIAN_POINT('',(-6.24779625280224,5.01619850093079,6.68620361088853));
#541=CARTESIAN_POINT('',(-6.21813895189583,5.0478612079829,6.66067187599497));
#542=CARTESIAN_POINT('',(-6.17033482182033,5.09973563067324,6.61900123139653));
#543=CARTESIAN_POINT('',(-6.15201397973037,5.11982116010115,6.60290481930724));
#544=CARTESIAN_POINT('',(-6.12244478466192,5.15257170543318,6.57667362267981));
#545=CARTESIAN_POINT('',(-6.11112210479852,5.16519318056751,6.56656814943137));
#546=CARTESIAN_POINT('',(-6.09283224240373,5.18571154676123,6.55006512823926));
#547=CARTESIAN_POINT('',(-6.08582724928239,5.1936015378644,6.54370123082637));
#548=CARTESIAN_POINT('',(-6.07451533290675,5.20639317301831,6.53324372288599));
#549=CARTESIAN_POINT('',(-6.07018138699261,5.21130628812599,6.52919336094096));
#550=CARTESIAN_POINT('',(-6.06319526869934,5.21924541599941,6.52245610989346));
#551=CARTESIAN_POINT('',(-6.06051754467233,5.22229316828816,6.51982285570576));
#552=CARTESIAN_POINT('',(-6.0562220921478,5.22718951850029,6.5153541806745));
#553=CARTESIAN_POINT('',(-6.0545755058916,5.22906827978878,6.51357999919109));
#554=CARTESIAN_POINT('',(-6.05195439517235,5.23206168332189,6.51048008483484));
#555=CARTESIAN_POINT('',(-6.05094876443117,5.23321085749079,6.50921868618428));
#556=CARTESIAN_POINT('',(-6.04953567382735,5.23482648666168,6.50715333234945));
#557=CARTESIAN_POINT('',(-6.04907752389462,5.23535045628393,6.50643002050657));
#558=CARTESIAN_POINT('',(-6.04823578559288,5.23631334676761,6.50488896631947));
#559=CARTESIAN_POINT('',(-6.04785159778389,5.23675295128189,6.50407207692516));
#560=CARTESIAN_POINT('',(-6.0474369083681,5.23722752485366,6.50283591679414));
#561=CARTESIAN_POINT('',(-6.04733310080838,5.23734633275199,6.50247536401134));
#562=CARTESIAN_POINT('',(-6.04716429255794,5.23753954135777,6.5017344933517));
#563=CARTESIAN_POINT('',(-6.04709913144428,5.2376141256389,6.5013542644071));
#564=CARTESIAN_POINT('',(-6.04703741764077,5.23768476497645,6.50077580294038));
#565=CARTESIAN_POINT('',(-6.04702284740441,5.2377014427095,6.5005818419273));
#566=CARTESIAN_POINT('',(-6.04700611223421,5.23772059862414,6.50019185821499));
#567=CARTESIAN_POINT('',(-6.04700400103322,5.23772301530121,6.49999583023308));
#568=CARTESIAN_POINT('',(-6.04700841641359,5.23771796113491,6.49979999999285));
#569=B_SPLINE_CURVE_WITH_KNOTS('',3,(#521,#522,#523,#524,#525,#526,#527,#528,#529,#530,#531,
#532,#533,#534,#535,#536,#537,#538,#539,#540,#541,#542,#543,#544,#545,#546,#547,#548,#549,#550,
#551,#552,#553,#554,#555,#556,#557,#558,#559,#560,#561,#562,#563,#564,#565,#566,#567,#568),
.UNSPECIFIED.,.F.,.F.,(4,2,2,2,2,2,2,2,2,2,2,2,2,2,2,2,2,2,2,2,2,2,2,4),(0.,0.292609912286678,
0.584635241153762,0.874589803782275,1.16467807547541,1.56824756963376,1.97218971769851,
2.53235699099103,2.90259343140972,3.14087410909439,3.29188442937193,3.38666478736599,
3.44588137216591,3.48284532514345,3.50595247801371,3.52045898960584,3.52964962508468,
3.535578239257,3.53858720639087,3.54157065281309,3.54274772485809,3.54391987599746,
3.54450469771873,3.54509203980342),.UNSPECIFIED.);
#570=EDGE_CURVE('E303',#518,#442,#569,.T.);
#571=ORIENTED_EDGE('',*,*,#570,.T.);
#572=EDGE_LOOP('',(#474,#475,#516,#520,#571));
#573=FACE_BOUND('',#572,.T.);
#574=ADVANCED_FACE('F315',(#573),#23,.F.);
#575=CARTESIAN_POINT('',(0.,0.,55.4157550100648));
#576=DIRECTION('',(0.,0.,1.));
#577=DIRECTION('',(0.,-1.,0.));
#578=AXIS2_PLACEMENT_3D('',#575,#576,#577);
#579=DEGENERATE_TOROIDAL_SURFACE('',#578,2.58841668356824,47.9877389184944,.T.);
#580=ORIENTED_EDGE('',*,*,#103,.T.);
#581=CARTESIAN_POINT('',(5.4068317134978,6.07621837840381,7.7494688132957));
#582=CARTESIAN_POINT('',(5.52812198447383,5.89347890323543,7.7429783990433));
#583=CARTESIAN_POINT('',(5.65700170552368,5.71570882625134,7.73854990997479));
#584=CARTESIAN_POINT('',(5.92894070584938,5.37132213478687,7.73380323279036));
#585=CARTESIAN_POINT('',(6.0719992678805,5.20470495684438,7.73348483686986));
#586=CARTESIAN_POINT('',(6.37122802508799,4.88390689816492,7.73694320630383));
#587=CARTESIAN_POINT('',(6.52739107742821,4.72971933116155,7.74071775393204));
#588=CARTESIAN_POINT('',(6.85176427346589,4.43476082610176,7.75240465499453));
#589=CARTESIAN_POINT('',(7.01997428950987,4.29398974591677,7.76031696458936));
#590=CARTESIAN_POINT('',(7.36783783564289,4.02636487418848,7.78038916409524));
#591=CARTESIAN_POINT('',(7.54752977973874,3.89956213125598,7.79256399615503));
#592=CARTESIAN_POINT('',(7.91649610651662,3.66131057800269,7.821236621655));
#593=CARTESIAN_POINT('',(8.10577067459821,3.54986206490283,7.83773449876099));
#594=CARTESIAN_POINT('',(8.49239482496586,3.34310822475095,7.87510081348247));
#595=CARTESIAN_POINT('',(8.68974003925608,3.24779430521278,7.89596691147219));
#596=CARTESIAN_POINT('',(9.09114269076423,3.07382646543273,7.94208905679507));
#597=CARTESIAN_POINT('',(9.29520008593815,2.99517244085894,7.96734507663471));
#598=CARTESIAN_POINT('',(9.708584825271,2.85494889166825,8.02221321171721));
#599=CARTESIAN_POINT('',(9.9179134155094,2.79338344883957,8.05182636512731));
#600=CARTESIAN_POINT('',(10.3403726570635,2.68763386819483,8.11531933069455));
#601=CARTESIAN_POINT('',(10.5535048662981,2.6434570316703,8.14920092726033));
#602=CARTESIAN_POINT('',(10.9821587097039,2.57264099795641,8.2210978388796));
#603=CARTESIAN_POINT('',(11.1976821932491,2.54601649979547,8.25911658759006));
#604=CARTESIAN_POINT('',(11.6293662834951,2.51038163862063,8.33904525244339));
#605=CARTESIAN_POINT('',(11.8455265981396,2.50136417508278,8.38095359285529));
#606=CARTESIAN_POINT('',(12.2817256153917,2.50079822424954,8.46936354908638));
#607=CARTESIAN_POINT('',(12.5017488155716,2.50962605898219,8.51594401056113));
#608=CARTESIAN_POINT('',(12.9395663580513,2.54525709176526,8.61262967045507));
#609=CARTESIAN_POINT('',(13.1573605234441,2.57206170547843,8.66273514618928));
#610=CARTESIAN_POINT('',(13.589081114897,2.64325392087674,8.76609695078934));
#611=CARTESIAN_POINT('',(13.8030107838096,2.68762598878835,8.81935046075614));
#612=CARTESIAN_POINT('',(14.225823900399,2.79346013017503,8.92868768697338));
#613=CARTESIAN_POINT('',(14.4347081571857,2.85491944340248,8.98477094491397));
#614=CARTESIAN_POINT('',(14.640416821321,2.92468299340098,9.0420974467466));
#615=B_SPLINE_CURVE_WITH_KNOTS('',3,(#581,#582,#583,#584,#585,#586,#587,#588,#589,#590,#591,
#592,#593,#594,#595,#596,#597,#598,#599,#600,#601,#602,#603,#604,#605,#606,#607,#608,#609,#610,
#611,#612,#613,#614),.UNSPECIFIED.,.F.,.F.,(4,2,2,2,2,2,2,2,2,2,2,2,2,2,2,2,4),(0.,
0.658072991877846,1.31611271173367,1.97379605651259,2.6314724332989,3.29147774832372,
3.95149583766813,4.61116132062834,5.27082267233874,5.93064145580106,6.59073699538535,
7.25138462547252,7.91176577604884,8.58621828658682,9.26072391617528,9.93463445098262,
10.6084361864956),.UNSPECIFIED.);
#616=CARTESIAN_POINT('',(13.1528156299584,2.57446317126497,8.6623511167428));
#617=VERTEX_POINT('',#616);
#618=EDGE_CURVE('E365',#93,#617,#615,.T.);
#619=ORIENTED_EDGE('',*,*,#618,.T.);
#620=CARTESIAN_POINT('',(13.1526156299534,2.57444288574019,8.66230481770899));
#621=CARTESIAN_POINT('',(13.9359553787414,2.65389517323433,8.84362255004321));
#622=CARTESIAN_POINT('',(14.7147354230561,2.73288498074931,9.04483639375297));
#623=CARTESIAN_POINT('',(16.259247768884,2.88954119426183,9.48592426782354));
#624=CARTESIAN_POINT('',(17.0250081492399,2.9672104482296,9.72569896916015));
#625=CARTESIAN_POINT('',(18.5435464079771,3.1212321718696,10.2437024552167));
#626=CARTESIAN_POINT('',(19.2963242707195,3.1975846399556,10.5219312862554));
#627=CARTESIAN_POINT('',(20.7888885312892,3.34897188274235,11.1168748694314));
#628=CARTESIAN_POINT('',(21.5286370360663,3.42400281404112,11.4336856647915));
#629=CARTESIAN_POINT('',(22.2599457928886,3.49817772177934,11.7690934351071));
#630=B_SPLINE_CURVE_WITH_KNOTS('',3,(#620,#621,#622,#623,#624,#625,#626,#627,#628,#629),
.UNSPECIFIED.,.F.,.F.,(4,2,2,2,4),(0.,2.42364073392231,4.84113555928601,7.25863329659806,
9.6822769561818),.UNSPECIFIED.);
#631=CARTESIAN_POINT('',(22.259509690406,3.49813348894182,11.7688934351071));
#632=VERTEX_POINT('',#631);
#633=EDGE_CURVE('E289',#617,#632,#630,.T.);
#634=ORIENTED_EDGE('',*,*,#633,.T.);
#635=CARTESIAN_POINT('',(0.,0.,11.7688934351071));
#636=DIRECTION('',(0.,0.,1.));
#637=DIRECTION('',(0.,-1.,0.));
#638=AXIS2_PLACEMENT_3D('',#635,#636,#637);
#639=CIRCLE('',#638,22.5327031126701);
#640=CARTESIAN_POINT('',(22.2597572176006,-3.49655804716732,11.7688934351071));
#641=VERTEX_POINT('',#640);
#642=EDGE_CURVE('E394',#641,#632,#639,.T.);
#643=ORIENTED_EDGE('',*,*,#642,.F.);
#644=CARTESIAN_POINT('',(12.9962083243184,-2.55398166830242,8.6261732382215));
#645=CARTESIAN_POINT('',(13.7932617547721,-2.63508273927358,8.80783637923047));
#646=CARTESIAN_POINT('',(14.5856701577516,-2.71571117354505,9.01008449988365));
#647=CARTESIAN_POINT('',(16.1570654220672,-2.87560238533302,9.45457114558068));
#648=CARTESIAN_POINT('',(16.9360820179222,-2.95486818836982,9.69670346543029));
#649=CARTESIAN_POINT('',(18.4807629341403,-3.11204118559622,10.220738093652));
#650=CARTESIAN_POINT('',(19.2464272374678,-3.18994837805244,10.5026404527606));
#651=CARTESIAN_POINT('',(20.7643941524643,-3.3444031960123,11.1062490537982));
#652=CARTESIAN_POINT('',(21.5166563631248,-3.42094671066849,11.4280579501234));
#653=CARTESIAN_POINT('',(22.2601932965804,-3.49660241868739,11.7690934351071));
#654=B_SPLINE_CURVE_WITH_KNOTS('',3,(#644,#645,#646,#647,#648,#649,#650,#651,#652,#653),
.UNSPECIFIED.,.F.,.F.,(4,2,2,2,4),(0.,2.46424751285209,4.9220361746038,7.37982797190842,
9.84407863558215),.UNSPECIFIED.);
#655=CARTESIAN_POINT('',(12.9964083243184,-2.55400201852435,8.6262188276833));
#656=VERTEX_POINT('',#655);
#657=EDGE_CURVE('E270',#656,#641,#654,.T.);
#658=ORIENTED_EDGE('',*,*,#657,.F.);
#659=CARTESIAN_POINT('',(5.40709709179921,-6.0762828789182,7.74949494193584));
#660=CARTESIAN_POINT('',(5.5283269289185,-5.8935500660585,7.74300062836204));
#661=CARTESIAN_POINT('',(5.65714597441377,-5.71578413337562,7.73856775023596));
#662=CARTESIAN_POINT('',(5.92896359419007,-5.37140070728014,7.73381126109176));
#663=CARTESIAN_POINT('',(6.07196145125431,-5.20478265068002,7.73348744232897));
#664=CARTESIAN_POINT('',(6.37106927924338,-4.88397779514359,7.73693388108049));
#665=CARTESIAN_POINT('',(6.5271721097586,-4.72978431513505,7.74070192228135));
#666=CARTESIAN_POINT('',(6.85142573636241,-4.43480905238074,7.75237463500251));
#667=CARTESIAN_POINT('',(7.01957640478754,-4.29402712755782,7.76027926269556));
#668=CARTESIAN_POINT('',(7.36732206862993,-4.02637592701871,7.78033479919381));
#669=CARTESIAN_POINT('',(7.54695546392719,-3.89955765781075,7.79250063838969));
#670=CARTESIAN_POINT('',(7.91580643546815,-3.66127029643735,7.82115395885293));
#671=CARTESIAN_POINT('',(8.10502419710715,-3.54980150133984,7.83764152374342));
#672=CARTESIAN_POINT('',(8.49153693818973,-3.34300255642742,7.87498590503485));
#673=CARTESIAN_POINT('',(8.68882754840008,-3.24766381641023,7.89584038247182));
#674=CARTESIAN_POINT('',(9.09012356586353,-3.07364203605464,7.94193802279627));
#675=CARTESIAN_POINT('',(9.29412893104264,-2.99495889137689,7.96718115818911));
#676=CARTESIAN_POINT('',(9.70741231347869,-2.85467316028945,8.02202231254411));
#677=CARTESIAN_POINT('',(9.91669157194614,-2.79307463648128,8.0516213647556));
#678=CARTESIAN_POINT('',(10.3390553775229,-2.68725515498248,8.11508504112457));
#679=CARTESIAN_POINT('',(10.5521414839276,-2.64304149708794,8.14895144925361));
#680=CARTESIAN_POINT('',(10.9807065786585,-2.57214841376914,8.22081700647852));
#681=CARTESIAN_POINT('',(11.1961874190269,-2.54548368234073,8.25881958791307));
#682=CARTESIAN_POINT('',(11.6277899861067,-2.50976534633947,8.3387150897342));
#683=CARTESIAN_POINT('',(11.8439114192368,-2.5007046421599,8.38060643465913));
#684=CARTESIAN_POINT('',(12.2800333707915,-2.50004860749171,8.4689808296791));
#685=CARTESIAN_POINT('',(12.5000184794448,-2.50882934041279,8.5155426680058));
#686=CARTESIAN_POINT('',(12.937764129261,-2.54436339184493,8.61219040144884));
#687=CARTESIAN_POINT('',(13.1555244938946,-2.571118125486,8.66227657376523));
#688=CARTESIAN_POINT('',(13.5871820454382,-2.64220826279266,8.76559927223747));
#689=CARTESIAN_POINT('',(13.8010824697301,-2.68652814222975,8.81883298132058));
#690=CARTESIAN_POINT('',(14.2238416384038,-2.79225594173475,8.92813021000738));
#691=CARTESIAN_POINT('',(14.432701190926,-2.85366110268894,8.98419327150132));
#692=CARTESIAN_POINT('',(14.638387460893,-2.92336970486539,9.0414994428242));
#693=B_SPLINE_CURVE_WITH_KNOTS('',3,(#659,#660,#661,#662,#663,#664,#665,#666,#667,#668,#669,
#670,#671,#672,#673,#674,#675,#676,#677,#678,#679,#680,#681,#682,#683,#684,#685,#686,#687,#688,
#689,#690,#691,#692),.UNSPECIFIED.,.F.,.F.,(4,2,2,2,2,2,2,2,2,2,2,2,2,2,2,2,4),(0.,
0.657956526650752,1.31587978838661,1.9734468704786,2.6310069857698,3.29089448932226,
3.95079476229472,4.61034248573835,5.26988607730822,5.92958636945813,6.58956337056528,
7.25009228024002,7.91035474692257,8.58467859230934,9.25905553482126,9.93283778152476,
10.6065112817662),.UNSPECIFIED.);
#694=EDGE_CURVE('E446',#656,#102,#693,.F.);
#695=ORIENTED_EDGE('',*,*,#694,.T.);
#696=EDGE_LOOP('',(#580,#619,#634,#643,#658,#695));
#697=FACE_BOUND('',#696,.T.);
#698=ADVANCED_FACE('F238',(#697),#579,.T.);
#699=CARTESIAN_POINT('',(0.,0.,19.5));
#700=DIRECTION('',(0.,0.,1.));
#701=DIRECTION('',(0.,-1.,0.));
#702=AXIS2_PLACEMENT_3D('',#699,#700,#701);
#703=TOROIDAL_SURFACE('',#702,19.,8.5);
#704=CARTESIAN_POINT('',(12.987061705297,-2.55305098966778,13.2532398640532));
#705=CARTESIAN_POINT('',(13.1631589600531,-2.57096908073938,13.0905697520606));
#706=CARTESIAN_POINT('',(13.3461181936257,-2.58958538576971,12.9354132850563));
#707=CARTESIAN_POINT('',(13.7243744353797,-2.628073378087,12.6411424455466));
#708=CARTESIAN_POINT('',(13.919670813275,-2.64794500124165,12.5020272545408));
#709=CARTESIAN_POINT('',(14.3210996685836,-2.68879083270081,12.2409239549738));
#710=CARTESIAN_POINT('',(14.5272248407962,-2.70976429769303,12.1189244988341));
#711=CARTESIAN_POINT('',(14.9489583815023,-2.75267615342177,11.8928014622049));
#712=CARTESIAN_POINT('',(15.1645666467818,-2.77461453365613,11.7886776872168));
#713=CARTESIAN_POINT('',(15.6037892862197,-2.819305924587,11.5990244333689));
#714=CARTESIAN_POINT('',(15.8274054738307,-2.84205911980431,11.5134991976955));
#715=CARTESIAN_POINT('',(16.2810131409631,-2.88821420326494,11.3616827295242));
#716=CARTESIAN_POINT('',(16.5110047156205,-2.91161610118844,11.2953917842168));
#717=CARTESIAN_POINT('',(16.9756772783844,-2.95889705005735,11.1825348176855));
#718=CARTESIAN_POINT('',(17.2103572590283,-2.9827759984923,11.1359646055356));
#719=CARTESIAN_POINT('',(17.6827856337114,-3.03084610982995,11.0628676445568));
#720=CARTESIAN_POINT('',(17.9205340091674,-3.0550372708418,11.0363407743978));
#721=CARTESIAN_POINT('',(18.3968348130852,-3.10350140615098,11.0035671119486));
#722=CARTESIAN_POINT('',(18.6353839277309,-3.12777404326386,10.9972716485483));
#723=CARTESIAN_POINT('',(19.1122457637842,-3.17629526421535,11.0048792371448));
#724=CARTESIAN_POINT('',(19.3505583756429,-3.20054383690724,11.0187892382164));
#725=CARTESIAN_POINT('',(19.8251638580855,-3.24883547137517,11.0667305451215));
#726=CARTESIAN_POINT('',(20.0614567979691,-3.27287854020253,11.1007611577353));
#727=CARTESIAN_POINT('',(20.530354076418,-3.32058935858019,11.1887115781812));
#728=CARTESIAN_POINT('',(20.7629583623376,-3.34425710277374,11.2426316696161));
#729=CARTESIAN_POINT('',(21.2228211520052,-3.3910486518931,11.3699875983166));
#730=CARTESIAN_POINT('',(21.4500795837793,-3.41417244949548,11.4434236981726));
#731=CARTESIAN_POINT('',(21.8976314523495,-3.4597113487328,11.6092990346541));
#732=CARTESIAN_POINT('',(22.1179247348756,-3.48212643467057,11.7017386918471));
#733=CARTESIAN_POINT('',(22.5499142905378,-3.52608185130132,11.9049442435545));
#734=CARTESIAN_POINT('',(22.7616126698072,-3.54762239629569,12.015705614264));
#735=CARTESIAN_POINT('',(23.1750285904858,-3.58968792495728,12.254829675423));
#736=CARTESIAN_POINT('',(23.3767426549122,-3.61021255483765,12.3831984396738));
#737=CARTESIAN_POINT('',(23.7683767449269,-3.65006175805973,12.6563952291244));
#738=CARTESIAN_POINT('',(23.9583137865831,-3.66938806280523,12.8011986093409));
#739=CARTESIAN_POINT('',(24.3253637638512,-3.70673580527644,13.1063940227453));
#740=CARTESIAN_POINT('',(24.5024765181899,-3.72475722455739,13.2667862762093));
#741=CARTESIAN_POINT('',(24.8426074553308,-3.75936592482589,13.6020182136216));
#742=CARTESIAN_POINT('',(25.0056256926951,-3.77595321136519,13.7768578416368));
#743=CARTESIAN_POINT('',(25.3164049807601,-3.80757534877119,14.1397457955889));
#744=CARTESIAN_POINT('',(25.4641657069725,-3.82261016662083,14.3277944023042));
#745=CARTESIAN_POINT('',(25.7431414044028,-3.85099625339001,14.7154435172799));
#746=CARTESIAN_POINT('',(25.8743827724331,-3.86435020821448,14.9150248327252));
#747=CARTESIAN_POINT('',(26.1197038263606,-3.88931189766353,15.3246683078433));
#748=CARTESIAN_POINT('',(26.2337775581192,-3.90091902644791,15.5347340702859));
#749=CARTESIAN_POINT('',(26.4438729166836,-3.92229646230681,15.9637467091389));
#750=CARTESIAN_POINT('',(26.5398979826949,-3.93206711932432,16.1826918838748));
#751=CARTESIAN_POINT('',(26.7132374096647,-3.94970459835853,16.627945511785));
#752=CARTESIAN_POINT('',(26.7905515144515,-3.95757139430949,16.8542540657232));
#753=CARTESIAN_POINT('',(26.9258508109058,-3.97133824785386,17.3124050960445));
#754=CARTESIAN_POINT('',(26.9838540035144,-3.977240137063,17.5442422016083));
#755=CARTESIAN_POINT('',(27.0802175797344,-3.98704523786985,18.012010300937));
#756=CARTESIAN_POINT('',(27.1185775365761,-3.99094840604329,18.2479413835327));
#757=CARTESIAN_POINT('',(27.175372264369,-3.99672733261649,18.722160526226));
#758=CARTESIAN_POINT('',(27.1938115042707,-3.99860354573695,18.9604480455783));
#759=CARTESIAN_POINT('',(27.2106520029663,-4.0003170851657,19.4378390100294));
#760=CARTESIAN_POINT('',(27.209044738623,-4.00015354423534,19.6769427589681));
#761=CARTESIAN_POINT('',(27.1857879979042,-3.99778714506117,20.1540619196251));
#762=CARTESIAN_POINT('',(27.1641469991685,-3.99558514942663,20.3920777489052));
#763=CARTESIAN_POINT('',(27.1010028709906,-3.98916016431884,20.865329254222));
#764=CARTESIAN_POINT('',(27.0595081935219,-3.98493803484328,21.1005660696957));
#765=CARTESIAN_POINT('',(26.9569448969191,-3.97450210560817,21.5667427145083));
#766=CARTESIAN_POINT('',(26.8958719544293,-3.96828786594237,21.7976815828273));
#767=CARTESIAN_POINT('',(26.7545922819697,-3.95391250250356,22.2535626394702));
#768=CARTESIAN_POINT('',(26.6743859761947,-3.94575142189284,22.4785049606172));
#769=CARTESIAN_POINT('',(26.4954052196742,-3.92753993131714,22.9208151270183));
#770=CARTESIAN_POINT('',(26.3966295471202,-3.91748939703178,23.1381824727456));
#771=CARTESIAN_POINT('',(26.1812196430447,-3.89557120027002,23.5637808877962));
#772=CARTESIAN_POINT('',(26.0645856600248,-3.88370356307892,23.7720120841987));
#773=CARTESIAN_POINT('',(25.814266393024,-3.85823329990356,24.1779020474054));
#774=CARTESIAN_POINT('',(25.6805779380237,-3.84463035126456,24.3755588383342));
#775=CARTESIAN_POINT('',(25.3971688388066,-3.81579316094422,24.7587904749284));
#776=CARTESIAN_POINT('',(25.2474537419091,-3.80055948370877,24.9443694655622));
#777=CARTESIAN_POINT('',(24.9329067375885,-3.76855397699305,25.3023348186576));
#778=CARTESIAN_POINT('',(24.7680640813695,-3.75178105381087,25.4747116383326));
#779=CARTESIAN_POINT('',(24.4245315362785,-3.71682623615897,25.8049014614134));
#780=CARTESIAN_POINT('',(24.2458419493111,-3.69864437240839,25.962714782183));
#781=CARTESIAN_POINT('',(23.875884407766,-3.66100078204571,26.262666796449));
#782=CARTESIAN_POINT('',(23.6846164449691,-3.6415390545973,26.4048054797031));
#783=CARTESIAN_POINT('',(23.2908656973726,-3.60147447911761,26.6724036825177));
#784=CARTESIAN_POINT('',(23.0883830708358,-3.58087164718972,26.7978634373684));
#785=CARTESIAN_POINT('',(22.6733932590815,-3.53864597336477,27.0313619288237));
#786=CARTESIAN_POINT('',(22.46087447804,-3.51702195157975,27.1393798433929));
#787=CARTESIAN_POINT('',(22.0276219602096,-3.47293802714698,27.3370210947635));
#788=CARTESIAN_POINT('',(21.8068910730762,-3.45047841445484,27.4266507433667));
#789=CARTESIAN_POINT('',(21.3586572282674,-3.40487012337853,27.5869549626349));
#790=CARTESIAN_POINT('',(21.1311526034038,-3.38172127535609,27.6576248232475));
#791=CARTESIAN_POINT('',(20.6710430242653,-3.33490461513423,27.7794869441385));
#792=CARTESIAN_POINT('',(20.4384381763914,-3.31123681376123,27.830679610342));
#793=CARTESIAN_POINT('',(19.9693993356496,-3.26351159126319,27.9133020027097));
#794=CARTESIAN_POINT('',(19.7329598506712,-3.23945361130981,27.9447002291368));
#795=CARTESIAN_POINT('',(19.2582948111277,-3.19115591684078,27.9873917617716));
#796=CARTESIAN_POINT('',(19.020069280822,-3.16691620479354,27.9986853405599));
#797=CARTESIAN_POINT('',(18.5435075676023,-3.11842552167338,28.0010981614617));
#798=CARTESIAN_POINT('',(18.3051713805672,-3.09417455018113,27.9922165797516));
#799=CARTESIAN_POINT('',(17.8301670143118,-3.04584232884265,27.9543561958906));
#800=CARTESIAN_POINT('',(17.5934982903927,-3.0217610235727,27.9253842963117));
#801=CARTESIAN_POINT('',(17.1229448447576,-2.97388168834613,27.8474855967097));
#802=CARTESIAN_POINT('',(16.8890666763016,-2.95008432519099,27.7985187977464));
#803=CARTESIAN_POINT('',(16.4262363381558,-2.90299082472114,27.6809828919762));
#804=CARTESIAN_POINT('',(16.1972841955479,-2.87969469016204,27.6124136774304));
#805=CARTESIAN_POINT('',(15.7458819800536,-2.8337640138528,27.4561485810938));
#806=CARTESIAN_POINT('',(15.5234332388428,-2.81112960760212,27.3684488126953));
#807=CARTESIAN_POINT('',(15.0866647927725,-2.76668793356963,27.1745570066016));
#808=CARTESIAN_POINT('',(14.8723449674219,-2.74488065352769,27.0683652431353));
#809=CARTESIAN_POINT('',(14.4531226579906,-2.70222431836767,26.8381161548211));
#810=CARTESIAN_POINT('',(14.2482306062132,-2.68137632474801,26.7140396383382));
#811=CARTESIAN_POINT('',(13.8495648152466,-2.64081163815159,26.4489854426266));
#812=CARTESIAN_POINT('',(13.6557911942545,-2.62109495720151,26.3080075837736));
#813=CARTESIAN_POINT('',(13.2806197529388,-2.58292084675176,26.010036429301));
#814=CARTESIAN_POINT('',(13.0992306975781,-2.56446430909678,25.8530319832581));
#815=CARTESIAN_POINT('',(12.7502490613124,-2.52895504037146,25.5242109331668));
#816=CARTESIAN_POINT('',(12.5826572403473,-2.51190238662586,25.352393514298));
#817=CARTESIAN_POINT('',(12.4226100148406,-2.49561740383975,25.1737389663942));
#818=B_SPLINE_CURVE_WITH_KNOTS('',3,(#704,#705,#706,#707,#708,#709,#710,#711,#712,#713,#714,
#715,#716,#717,#718,#719,#720,#721,#722,#723,#724,#725,#726,#727,#728,#729,#730,#731,#732,#733,
#734,#735,#736,#737,#738,#739,#740,#741,#742,#743,#744,#745,#746,#747,#748,#749,#750,#751,#752,
#753,#754,#755,#756,#757,#758,#759,#760,#761,#762,#763,#764,#765,#766,#767,#768,#769,#770,#771,
#772,#773,#774,#775,#776,#777,#778,#779,#780,#781,#782,#783,#784,#785,#786,#787,#788,#789,#790,
#791,#792,#793,#794,#795,#796,#797,#798,#799,#800,#801,#802,#803,#804,#805,#806,#807,#808,#809,
#810,#811,#812,#813,#814,#815,#816,#817),.UNSPECIFIED.,.F.,.F.,(4,2,2,2,2,2,2,2,2,2,2,2,2,2,2,2,
2,2,2,2,2,2,2,2,2,2,2,2,2,2,2,2,2,2,2,2,2,2,2,2,2,2,2,2,2,2,2,2,2,2,2,2,2,2,2,2,4),(0.,
0.720982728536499,1.44192865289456,2.16239431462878,2.88285213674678,3.60347415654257,
4.32410693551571,5.04458649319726,5.76506168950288,6.4838023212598,7.20279020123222,
7.92175331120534,8.64072667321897,9.35970970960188,10.0787086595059,10.7975303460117,
11.5166006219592,12.2346064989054,12.9526225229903,13.6706357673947,14.3886642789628,
15.1055304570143,15.822644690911,16.5396221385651,17.2566094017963,17.9729264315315,
18.6892590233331,19.4054308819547,20.1219072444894,20.8380805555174,21.5539492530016,
22.2699761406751,22.9859871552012,23.7020452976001,24.418093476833,25.1342749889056,
25.8502094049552,26.5666565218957,27.2830880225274,27.9995199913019,28.7159418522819,
29.4332127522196,30.1502370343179,30.8674392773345,31.5846265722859,32.302952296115,
33.0212682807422,33.7396135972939,34.4577122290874,35.1772544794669,35.8968006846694,
36.6164932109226,37.3361750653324,38.056635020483,38.7771026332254,39.4980749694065,
40.219086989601),.UNSPECIFIED.);
#819=EDGE_CURVE('E247',#641,#204,#818,.T.);
#820=ORIENTED_EDGE('',*,*,#819,.F.);
#821=ORIENTED_EDGE('',*,*,#642,.T.);
#822=CARTESIAN_POINT('',(22.2590735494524,3.49808925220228,11.7686934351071));
#823=CARTESIAN_POINT('',(22.4756259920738,3.52005365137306,11.8679615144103));
#824=CARTESIAN_POINT('',(22.6879921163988,3.54159344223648,11.9764461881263));
#825=CARTESIAN_POINT('',(23.1028851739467,3.58367505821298,12.2109811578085));
#826=CARTESIAN_POINT('',(23.3054125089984,3.6042169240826,12.3370307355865));
#827=CARTESIAN_POINT('',(23.6990493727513,3.64414257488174,12.6057474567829));
#828=CARTESIAN_POINT('',(23.890166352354,3.66352711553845,12.7484035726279));
#829=CARTESIAN_POINT('',(24.2597672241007,3.7010148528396,13.049383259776));
#830=CARTESIAN_POINT('',(24.4382512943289,3.71911806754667,13.2077066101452));
#831=CARTESIAN_POINT('',(24.7814012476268,3.7539229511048,13.5389866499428));
#832=CARTESIAN_POINT('',(24.9460601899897,3.77062391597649,13.7119506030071));
#833=CARTESIAN_POINT('',(25.2602867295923,3.80249516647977,14.0712185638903));
#834=CARTESIAN_POINT('',(25.4098541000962,3.81766542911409,14.2575227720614));
#835=CARTESIAN_POINT('',(25.6927947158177,3.84636342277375,14.6421035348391));
#836=CARTESIAN_POINT('',(25.8261714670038,3.85989150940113,14.840377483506));
#837=CARTESIAN_POINT('',(26.0758143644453,3.88521219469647,15.2475234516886));
#838=CARTESIAN_POINT('',(26.1920806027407,3.89700480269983,15.4563954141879));
#839=CARTESIAN_POINT('',(26.4065635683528,3.91875929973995,15.8830368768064));
#840=CARTESIAN_POINT('',(26.5047983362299,3.92872301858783,16.1007972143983));
#841=CARTESIAN_POINT('',(26.6826917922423,3.9467663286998,16.5439411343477));
#842=CARTESIAN_POINT('',(26.7623440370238,3.95484526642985,16.7693273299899));
#843=CARTESIAN_POINT('',(26.9024572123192,3.96905661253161,17.2260407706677));
#844=CARTESIAN_POINT('',(26.9629186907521,3.97518907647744,17.4573678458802));
#845=CARTESIAN_POINT('',(27.0642218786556,3.98546401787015,17.9243259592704));
#846=CARTESIAN_POINT('',(27.1050632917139,3.98960646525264,18.1599570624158));
#847=CARTESIAN_POINT('',(27.1668094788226,3.99586923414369,18.6336620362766));
#848=CARTESIAN_POINT('',(27.1877293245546,3.99799108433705,18.8717339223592));
#849=CARTESIAN_POINT('',(27.2095367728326,4.00020296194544,19.3488080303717));
#850=CARTESIAN_POINT('',(27.2104239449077,4.00029294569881,19.5878102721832));
#851=CARTESIAN_POINT('',(27.1921608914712,3.99844056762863,20.0649803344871));
#852=CARTESIAN_POINT('',(27.1730156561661,3.99649871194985,20.3031483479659));
#853=CARTESIAN_POINT('',(27.114822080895,3.99059627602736,20.7770988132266));
#854=CARTESIAN_POINT('',(27.0757668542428,3.98663499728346,21.0128804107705));
#855=CARTESIAN_POINT('',(26.9780464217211,3.9767234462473,21.4802118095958));
#856=CARTESIAN_POINT('',(26.9193883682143,3.97077389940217,21.7117631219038));
#857=CARTESIAN_POINT('',(26.7828759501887,3.95692776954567,22.1690818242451));
#858=CARTESIAN_POINT('',(26.7050211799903,3.94903114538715,22.3948490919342));
#859=CARTESIAN_POINT('',(26.5306716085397,3.93134728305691,22.8389906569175));
#860=CARTESIAN_POINT('',(26.4341768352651,3.92156004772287,23.0573649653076));
#861=CARTESIAN_POINT('',(26.2232332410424,3.90016454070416,23.4851753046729));
#862=CARTESIAN_POINT('',(26.1087840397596,3.88855623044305,23.6946111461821));
#863=CARTESIAN_POINT('',(25.862717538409,3.86359829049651,24.103106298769));
#864=CARTESIAN_POINT('',(25.7310958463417,3.85024821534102,24.3021629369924));
#865=CARTESIAN_POINT('',(25.4516455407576,3.82190423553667,24.6884305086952));
#866=CARTESIAN_POINT('',(25.3038169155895,3.80691032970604,24.8756414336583));
#867=CARTESIAN_POINT('',(24.9930052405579,3.77538544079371,25.2368924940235));
#868=CARTESIAN_POINT('',(24.8300220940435,3.75885444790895,25.4109325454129));
#869=CARTESIAN_POINT('',(24.4900663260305,3.72437354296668,25.7446059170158));
#870=CARTESIAN_POINT('',(24.3130939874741,3.70642365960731,25.9042395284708));
#871=CARTESIAN_POINT('',(23.9462722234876,3.66921780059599,26.2080957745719));
#872=CARTESIAN_POINT('',(23.7564128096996,3.64996081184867,26.3523062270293));
#873=CARTESIAN_POINT('',(23.3652965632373,3.61029082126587,26.6241517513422));
#874=CARTESIAN_POINT('',(23.1640399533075,3.58987784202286,26.7517871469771));
#875=CARTESIAN_POINT('',(22.7515165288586,3.54803657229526,26.9896105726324));
#876=CARTESIAN_POINT('',(22.5402477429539,3.52660808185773,27.0997951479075));
#877=CARTESIAN_POINT('',(22.1093128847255,3.48289938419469,27.3018777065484));
#878=CARTESIAN_POINT('',(21.8896497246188,3.46061947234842,27.3937819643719));
#879=CARTESIAN_POINT('',(21.4430798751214,3.41532495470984,27.5588329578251));
#880=CARTESIAN_POINT('',(21.2161627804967,3.39230929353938,27.6319512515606));
#881=CARTESIAN_POINT('',(20.7570180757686,3.34573933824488,27.7587378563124));
#882=CARTESIAN_POINT('',(20.5247905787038,3.32218505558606,27.8124065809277));
#883=CARTESIAN_POINT('',(20.0566831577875,3.27470603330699,27.8999225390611));
#884=CARTESIAN_POINT('',(19.8208034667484,3.25078131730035,27.9337710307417));
#885=CARTESIAN_POINT('',(19.347051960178,3.20272982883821,27.9814216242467));
#886=CARTESIAN_POINT('',(19.1091801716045,3.17860305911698,27.9952239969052));
#887=CARTESIAN_POINT('',(18.6327102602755,3.13027584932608,28.0027018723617));
#888=CARTESIAN_POINT('',(18.3941115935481,3.10607535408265,27.9963423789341));
#889=CARTESIAN_POINT('',(17.9183738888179,3.05782241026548,27.9634803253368));
#890=CARTESIAN_POINT('',(17.68123437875,3.03376991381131,27.9369846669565));
#891=CARTESIAN_POINT('',(17.209852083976,2.98595872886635,27.8640304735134));
#892=CARTESIAN_POINT('',(16.9756113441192,2.96220024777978,27.8175585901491));
#893=CARTESIAN_POINT('',(16.5118545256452,2.91516249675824,27.704988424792));
#894=CARTESIAN_POINT('',(16.2823382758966,2.89188320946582,27.6388908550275));
#895=CARTESIAN_POINT('',(15.8290313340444,2.84590536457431,27.4873377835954));
#896=CARTESIAN_POINT('',(15.6052578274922,2.82320855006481,27.4018303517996));
#897=CARTESIAN_POINT('',(15.1656771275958,2.77862292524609,27.2121704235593));
#898=CARTESIAN_POINT('',(14.949869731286,2.75673409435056,27.1080184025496));
#899=CARTESIAN_POINT('',(14.528132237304,2.7139582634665,26.8820175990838));
#900=CARTESIAN_POINT('',(14.3221853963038,2.69306956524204,26.7602003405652));
#901=CARTESIAN_POINT('',(13.9213042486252,2.65240914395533,26.4996379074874));
#902=CARTESIAN_POINT('',(13.7263634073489,2.63263675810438,26.360902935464));
#903=CARTESIAN_POINT('',(13.4718918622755,2.60682631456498,26.1631370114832));
#904=CARTESIAN_POINT('',(13.406907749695,2.60023513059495,26.1110850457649));
#905=CARTESIAN_POINT('',(13.2785583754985,2.58721695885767,26.005148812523));
#906=CARTESIAN_POINT('',(13.2151913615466,2.58078979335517,25.9512666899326));
#907=CARTESIAN_POINT('',(13.1526156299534,2.57444288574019,25.8964578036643));
#908=B_SPLINE_CURVE_WITH_KNOTS('',3,(#822,#823,#824,#825,#826,#827,#828,#829,#830,#831,#832,
#833,#834,#835,#836,#837,#838,#839,#840,#841,#842,#843,#844,#845,#846,#847,#848,#849,#850,#851,
#852,#853,#854,#855,#856,#857,#858,#859,#860,#861,#862,#863,#864,#865,#866,#867,#868,#869,#870,
#871,#872,#873,#874,#875,#876,#877,#878,#879,#880,#881,#882,#883,#884,#885,#886,#887,#888,#889,
#890,#891,#892,#893,#894,#895,#896,#897,#898,#899,#900,#901,#902,#903,#904,#905,#906,#907),
.UNSPECIFIED.,.F.,.F.,(4,2,2,2,2,2,2,2,2,2,2,2,2,2,2,2,2,2,2,2,2,2,2,2,2,2,2,2,2,2,2,2,2,2,2,2,
2,2,2,2,2,2,4),(0.,0.717475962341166,1.4349225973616,2.15189550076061,2.86885829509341,
3.58617890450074,4.30351028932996,5.02068606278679,5.73785797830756,6.45430840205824,
7.17100688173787,7.88768489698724,8.60437373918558,9.32051993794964,10.0366815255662,
10.7526647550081,11.468895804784,12.1848658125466,12.900850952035,13.6168350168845,
14.3328342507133,15.0490169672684,15.7652001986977,16.4813879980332,17.1975613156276,
17.9142961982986,18.6310170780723,19.3478796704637,20.064495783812,20.7821905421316,
21.4998700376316,22.2175039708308,22.9351282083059,23.6539987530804,24.3726230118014,
25.0917282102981,25.8108073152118,26.5318334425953,27.2528411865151,27.9725777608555,
28.6918824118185,28.9424193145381,29.192672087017),.UNSPECIFIED.);
#909=EDGE_CURVE('E252',#632,#213,#908,.T.);
#910=ORIENTED_EDGE('',*,*,#909,.T.);
#911=ORIENTED_EDGE('',*,*,#214,.F.);
#912=EDGE_LOOP('',(#820,#821,#910,#911));
#913=FACE_BOUND('',#912,.T.);
#914=ADVANCED_FACE('F233',(#913),#703,.T.);
#915=CARTESIAN_POINT('',(-22.2590735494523,3.49808925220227,11.7686934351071));
#916=CARTESIAN_POINT('',(-22.4756259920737,3.52005365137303,11.8679615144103));
#917=CARTESIAN_POINT('',(-22.6879921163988,3.54159344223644,11.9764461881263));
#918=CARTESIAN_POINT('',(-23.1028851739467,3.58367505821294,12.2109811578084));
#919=CARTESIAN_POINT('',(-23.3054125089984,3.60421692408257,12.3370307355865));
#920=CARTESIAN_POINT('',(-23.6990493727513,3.6441425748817,12.6057474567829));
#921=CARTESIAN_POINT('',(-23.890166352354,3.66352711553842,12.7484035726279));
#922=CARTESIAN_POINT('',(-24.2597672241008,3.70101485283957,13.0493832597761));
#923=CARTESIAN_POINT('',(-24.438251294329,3.71911806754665,13.2077066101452));
#924=CARTESIAN_POINT('',(-24.7814012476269,3.75392295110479,13.5389866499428));
#925=CARTESIAN_POINT('',(-24.9460601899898,3.77062391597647,13.7119506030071));
#926=CARTESIAN_POINT('',(-25.2602867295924,3.80249516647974,14.0712185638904));
#927=CARTESIAN_POINT('',(-25.4098541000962,3.81766542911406,14.2575227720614));
#928=CARTESIAN_POINT('',(-25.6927947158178,3.84636342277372,14.6421035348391));
#929=CARTESIAN_POINT('',(-25.8261714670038,3.85989150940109,14.8403774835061));
#930=CARTESIAN_POINT('',(-26.0758143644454,3.88521219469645,15.2475234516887));
#931=CARTESIAN_POINT('',(-26.1920806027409,3.89700480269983,15.4563954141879));
#932=CARTESIAN_POINT('',(-26.406563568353,3.91875929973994,15.8830368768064));
#933=CARTESIAN_POINT('',(-26.50479833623,3.9287230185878,16.1007972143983));
#934=CARTESIAN_POINT('',(-26.6826917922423,3.94676632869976,16.5439411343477));
#935=CARTESIAN_POINT('',(-26.7623440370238,3.95484526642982,16.7693273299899));
#936=CARTESIAN_POINT('',(-26.9024572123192,3.96905661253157,17.2260407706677));
#937=CARTESIAN_POINT('',(-26.9629186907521,3.9751890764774,17.4573678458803));
#938=CARTESIAN_POINT('',(-27.0642218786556,3.98546401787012,17.9243259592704));
#939=CARTESIAN_POINT('',(-27.105063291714,3.98960646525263,18.1599570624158));
#940=CARTESIAN_POINT('',(-27.1668094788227,3.99586923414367,18.6336620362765));
#941=CARTESIAN_POINT('',(-27.1877293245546,3.99799108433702,18.8717339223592));
#942=CARTESIAN_POINT('',(-27.2095367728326,4.0002029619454,19.3488080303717));
#943=CARTESIAN_POINT('',(-27.2104239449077,4.00029294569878,19.5878102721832));
#944=CARTESIAN_POINT('',(-27.1921608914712,3.99844056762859,20.0649803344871));
#945=CARTESIAN_POINT('',(-27.1730156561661,3.99649871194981,20.3031483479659));
#946=CARTESIAN_POINT('',(-27.114822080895,3.99059627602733,20.7770988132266));
#947=CARTESIAN_POINT('',(-27.0757668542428,3.98663499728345,21.0128804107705));
#948=CARTESIAN_POINT('',(-26.9780464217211,3.97672344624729,21.4802118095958));
#949=CARTESIAN_POINT('',(-26.9193883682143,3.97077389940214,21.7117631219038));
#950=CARTESIAN_POINT('',(-26.7828759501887,3.95692776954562,22.1690818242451));
#951=CARTESIAN_POINT('',(-26.7050211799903,3.94903114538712,22.3948490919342));
#952=CARTESIAN_POINT('',(-26.5306716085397,3.93134728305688,22.8389906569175));
#953=CARTESIAN_POINT('',(-26.4341768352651,3.92156004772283,23.0573649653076));
#954=CARTESIAN_POINT('',(-26.2232332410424,3.90016454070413,23.4851753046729));
#955=CARTESIAN_POINT('',(-26.1087840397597,3.88855623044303,23.6946111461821));
#956=CARTESIAN_POINT('',(-25.8627175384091,3.86359829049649,24.103106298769));
#957=CARTESIAN_POINT('',(-25.7310958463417,3.85024821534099,24.3021629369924));
#958=CARTESIAN_POINT('',(-25.4516455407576,3.82190423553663,24.6884305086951));
#959=CARTESIAN_POINT('',(-25.3038169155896,3.80691032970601,24.8756414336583));
#960=CARTESIAN_POINT('',(-24.9930052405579,3.77538544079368,25.2368924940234));
#961=CARTESIAN_POINT('',(-24.8300220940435,3.75885444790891,25.4109325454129));
#962=CARTESIAN_POINT('',(-24.4900663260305,3.72437354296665,25.7446059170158));
#963=CARTESIAN_POINT('',(-24.3130939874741,3.7064236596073,25.9042395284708));
#964=CARTESIAN_POINT('',(-23.9462722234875,3.66921780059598,26.2080957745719));
#965=CARTESIAN_POINT('',(-23.7564128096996,3.64996081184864,26.3523062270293));
#966=CARTESIAN_POINT('',(-23.3652965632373,3.61029082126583,26.6241517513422));
#967=CARTESIAN_POINT('',(-23.1640399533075,3.58987784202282,26.7517871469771));
#968=CARTESIAN_POINT('',(-22.7515165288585,3.54803657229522,26.9896105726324));
#969=CARTESIAN_POINT('',(-22.5402477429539,3.52660808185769,27.0997951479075));
#970=CARTESIAN_POINT('',(-22.1093128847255,3.48289938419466,27.3018777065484));
#971=CARTESIAN_POINT('',(-21.8896497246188,3.46061947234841,27.3937819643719));
#972=CARTESIAN_POINT('',(-21.4430798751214,3.41532495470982,27.5588329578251));
#973=CARTESIAN_POINT('',(-21.2161627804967,3.39230929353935,27.6319512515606));
#974=CARTESIAN_POINT('',(-20.7570180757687,3.34573933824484,27.7587378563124));
#975=CARTESIAN_POINT('',(-20.5247905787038,3.32218505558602,27.8124065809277));
#976=CARTESIAN_POINT('',(-20.0566831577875,3.27470603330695,27.8999225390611));
#977=CARTESIAN_POINT('',(-19.8208034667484,3.25078131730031,27.9337710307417));
#978=CARTESIAN_POINT('',(-19.347051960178,3.20272982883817,27.9814216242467));
#979=CARTESIAN_POINT('',(-19.1091801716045,3.17860305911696,27.9952239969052));
#980=CARTESIAN_POINT('',(-18.6327102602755,3.13027584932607,28.0027018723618));
#981=CARTESIAN_POINT('',(-18.3941115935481,3.10607535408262,27.9963423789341));
#982=CARTESIAN_POINT('',(-17.918373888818,3.05782241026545,27.9634803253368));
#983=CARTESIAN_POINT('',(-17.6812343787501,3.03376991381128,27.9369846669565));
#984=CARTESIAN_POINT('',(-17.2098520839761,2.98595872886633,27.8640304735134));
#985=CARTESIAN_POINT('',(-16.9756113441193,2.96220024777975,27.8175585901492));
#986=CARTESIAN_POINT('',(-16.5118545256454,2.91516249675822,27.704988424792));
#987=CARTESIAN_POINT('',(-16.2823382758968,2.89188320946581,27.6388908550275));
#988=CARTESIAN_POINT('',(-15.8290313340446,2.8459053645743,27.4873377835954));
#989=CARTESIAN_POINT('',(-15.6052578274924,2.82320855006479,27.4018303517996));
#990=CARTESIAN_POINT('',(-15.165677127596,2.77862292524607,27.2121704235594));
#991=CARTESIAN_POINT('',(-14.9498697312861,2.75673409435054,27.1080184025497));
#992=CARTESIAN_POINT('',(-14.5281322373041,2.71395826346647,26.8820175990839));
#993=CARTESIAN_POINT('',(-14.3221853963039,2.69306956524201,26.7602003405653));
#994=CARTESIAN_POINT('',(-13.9213042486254,2.65240914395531,26.4996379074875));
#995=CARTESIAN_POINT('',(-13.7263634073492,2.63263675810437,26.360902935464));
#996=CARTESIAN_POINT('',(-13.4718918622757,2.60682631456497,26.1631370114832));
#997=CARTESIAN_POINT('',(-13.4069077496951,2.60023513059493,26.111085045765));
#998=CARTESIAN_POINT('',(-13.2785583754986,2.58721695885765,26.0051488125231));
#999=CARTESIAN_POINT('',(-13.2151913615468,2.58078979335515,25.9512666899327));
#1000=CARTESIAN_POINT('',(-13.1526156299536,2.57444288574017,25.8964578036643));
#1001=B_SPLINE_CURVE_WITH_KNOTS('',3,(#915,#916,#917,#918,#919,#920,#921,#922,#923,#924,#925,
#926,#927,#928,#929,#930,#931,#932,#933,#934,#935,#936,#937,#938,#939,#940,#941,#942,#943,#944,
#945,#946,#947,#948,#949,#950,#951,#952,#953,#954,#955,#956,#957,#958,#959,#960,#961,#962,#963,
#964,#965,#966,#967,#968,#969,#970,#971,#972,#973,#974,#975,#976,#977,#978,#979,#980,#981,#982,
#983,#984,#985,#986,#987,#988,#989,#990,#991,#992,#993,#994,#995,#996,#997,#998,#999,#1000),
.UNSPECIFIED.,.F.,.F.,(4,2,2,2,2,2,2,2,2,2,2,2,2,2,2,2,2,2,2,2,2,2,2,2,2,2,2,2,2,2,2,2,2,2,2,2,
2,2,2,2,2,2,4),(0.,0.717475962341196,1.43492259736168,2.15189550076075,2.86885829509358,
3.58617890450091,4.30351028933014,5.02068606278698,5.73785797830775,6.4543084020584,
7.17100688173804,7.88768489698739,8.60437373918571,9.32051993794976,10.0366815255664,
10.7526647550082,11.4688958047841,12.1848658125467,12.9008509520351,13.6168350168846,
14.3328342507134,15.0490169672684,15.7652001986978,16.4813879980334,17.1975613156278,
17.9142961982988,18.6310170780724,19.3478796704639,20.0644957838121,20.7821905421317,
21.4998700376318,22.2175039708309,22.9351282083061,23.6539987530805,24.3726230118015,
25.0917282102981,25.8108073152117,26.5318334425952,27.252841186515,27.9725777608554,
28.6918824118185,28.942419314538,29.192672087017),.UNSPECIFIED.);
#1002=CARTESIAN_POINT('',(-22.259509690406,3.4981334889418,11.7688934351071));
#1003=VERTEX_POINT('',#1002);
#1004=EDGE_CURVE('E217',#1003,#306,#1001,.T.);
#1005=ORIENTED_EDGE('',*,*,#1004,.F.);
#1006=CARTESIAN_POINT('',(-22.2597572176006,-3.49655804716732,11.7688934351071));
#1007=VERTEX_POINT('',#1006);
#1008=EDGE_CURVE('E393',#1003,#1007,#639,.T.);
#1009=ORIENTED_EDGE('',*,*,#1008,.T.);
#1010=CARTESIAN_POINT('',(-12.9870618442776,-2.55305100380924,13.2532397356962));
#1011=CARTESIAN_POINT('',(-13.1631591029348,-2.57096909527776,13.0905696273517));
#1012=CARTESIAN_POINT('',(-13.3461183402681,-2.58958540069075,12.9354131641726));
#1013=CARTESIAN_POINT('',(-13.7243745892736,-2.62807339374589,12.6411423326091));
#1014=CARTESIAN_POINT('',(-13.9196709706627,-2.64794501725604,12.5020271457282));
#1015=CARTESIAN_POINT('',(-14.3210998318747,-2.68879084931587,12.2409238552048));
#1016=CARTESIAN_POINT('',(-14.5272250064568,-2.7097643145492,12.1189244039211));
#1017=CARTESIAN_POINT('',(-14.9489585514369,-2.75267617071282,11.8928013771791));
#1018=CARTESIAN_POINT('',(-15.1645668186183,-2.77461455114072,11.7886776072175));
#1019=CARTESIAN_POINT('',(-15.6037893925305,-2.81930593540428,11.5990243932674));
#1020=CARTESIAN_POINT('',(-15.8274055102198,-2.84205912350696,11.5134991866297));
#1021=CARTESIAN_POINT('',(-16.2810130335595,-2.88821419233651,11.3616827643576));
#1022=CARTESIAN_POINT('',(-16.511004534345,-2.91161608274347,11.2953918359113));
#1023=CARTESIAN_POINT('',(-16.9756769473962,-2.95889701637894,11.1825348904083));
#1024=CARTESIAN_POINT('',(-17.2103568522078,-2.98277595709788,11.1359646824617));
#1025=CARTESIAN_POINT('',(-17.68278507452,-3.03084605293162,11.062867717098));
#1026=CARTESIAN_POINT('',(-17.9205333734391,-3.05503720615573,11.0363408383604));
#1027=CARTESIAN_POINT('',(-18.3968341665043,-3.10350134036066,11.0035671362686));
#1028=CARTESIAN_POINT('',(-18.6353833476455,-3.12777398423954,10.9972716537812));
#1029=CARTESIAN_POINT('',(-19.1122453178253,-3.17629521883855,11.0048792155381));
#1030=CARTESIAN_POINT('',(-19.3505579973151,-3.20054379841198,11.0187892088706));
#1031=CARTESIAN_POINT('',(-19.8251636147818,-3.24883544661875,11.0667305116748));
#1032=CARTESIAN_POINT('',(-20.0614566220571,-3.27287852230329,11.1007611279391));
#1033=CARTESIAN_POINT('',(-20.530354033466,-3.32058935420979,11.1887115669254));
#1034=CARTESIAN_POINT('',(-20.7629583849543,-3.34425710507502,11.2426316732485));
#1035=CARTESIAN_POINT('',(-21.2228212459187,-3.39104866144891,11.3699876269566));
#1036=CARTESIAN_POINT('',(-21.450079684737,-3.41417245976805,11.4434237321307));
#1037=CARTESIAN_POINT('',(-21.8976315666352,-3.4597113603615,11.6092990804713));
#1038=CARTESIAN_POINT('',(-22.1179248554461,-3.48212644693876,11.7017387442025));
#1039=CARTESIAN_POINT('',(-22.5499144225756,-3.52608186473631,11.9049443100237));
#1040=CARTESIAN_POINT('',(-22.7616128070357,-3.54762241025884,12.0157056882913));
#1041=CARTESIAN_POINT('',(-23.1750287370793,-3.58968793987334,12.2548297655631));
#1042=CARTESIAN_POINT('',(-23.3767428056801,-3.61021257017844,12.3831985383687));
#1043=CARTESIAN_POINT('',(-23.7683768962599,-3.65006177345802,12.6563953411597));
#1044=CARTESIAN_POINT('',(-23.9583139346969,-3.66938807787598,12.8011987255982));
#1045=CARTESIAN_POINT('',(-24.3253639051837,-3.70673581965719,13.1063941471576));
#1046=CARTESIAN_POINT('',(-24.5024766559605,-3.7247572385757,13.2667864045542));
#1047=CARTESIAN_POINT('',(-24.8426075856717,-3.75936593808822,13.6020183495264));
#1048=CARTESIAN_POINT('',(-25.0056258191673,-3.77595322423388,13.7768579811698));
#1049=CARTESIAN_POINT('',(-25.3164050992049,-3.80757536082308,14.1397459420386));
#1050=CARTESIAN_POINT('',(-25.4641658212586,-3.82261017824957,14.3277945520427));
#1051=CARTESIAN_POINT('',(-25.7431415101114,-3.85099626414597,14.715443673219));
#1052=CARTESIAN_POINT('',(-25.8743828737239,-3.86435021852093,14.9150249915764));
#1053=CARTESIAN_POINT('',(-26.1197039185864,-3.88931190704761,15.3246684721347));
#1054=CARTESIAN_POINT('',(-26.2337776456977,-3.90091903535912,15.5347342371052));
#1055=CARTESIAN_POINT('',(-26.443872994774,-3.9222964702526,15.9637468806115));
#1056=CARTESIAN_POINT('',(-26.5398980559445,-3.93206712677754,16.1826920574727));
#1057=CARTESIAN_POINT('',(-26.7132374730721,-3.94970460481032,16.6279456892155));
#1058=CARTESIAN_POINT('',(-26.7905515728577,-3.9575714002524,16.854254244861));
#1059=CARTESIAN_POINT('',(-26.9258508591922,-3.97133825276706,17.3124052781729));
#1060=CARTESIAN_POINT('',(-26.9838540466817,-3.97724014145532,17.5442423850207));
#1061=CARTESIAN_POINT('',(-27.0802176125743,-3.98704524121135,18.0120104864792));
#1062=CARTESIAN_POINT('',(-27.1185775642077,-3.99094840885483,18.2479415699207));
#1063=CARTESIAN_POINT('',(-27.1753722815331,-3.99672733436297,18.7221607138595));
#1064=CARTESIAN_POINT('',(-27.1938115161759,-3.99860354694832,18.9604482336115));
#1065=CARTESIAN_POINT('',(-27.2106520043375,-4.00031708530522,19.4378391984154));
#1066=CARTESIAN_POINT('',(-27.2090447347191,-4.0001535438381,19.6769429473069));
#1067=CARTESIAN_POINT('',(-27.1857879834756,-3.99778714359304,20.1540621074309));
#1068=CARTESIAN_POINT('',(-27.1641469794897,-3.99558514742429,20.3920779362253));
#1069=CARTESIAN_POINT('',(-27.1010028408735,-3.9891601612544,20.8653294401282));
#1070=CARTESIAN_POINT('',(-27.0595081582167,-3.98493803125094,21.1005662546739));
#1071=CARTESIAN_POINT('',(-26.9569448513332,-3.97450210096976,21.5667428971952));
#1072=CARTESIAN_POINT('',(-26.8958719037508,-3.96828786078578,21.7976817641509));
#1073=CARTESIAN_POINT('',(-26.7545922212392,-3.95391249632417,22.2535628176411));
#1074=CARTESIAN_POINT('',(-26.6743859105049,-3.94575141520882,22.4785051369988));
#1075=CARTESIAN_POINT('',(-26.495405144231,-3.9275399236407,22.9208152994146));
#1076=CARTESIAN_POINT('',(-26.3966294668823,-3.91748938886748,23.1381826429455));
#1077=CARTESIAN_POINT('',(-26.1812195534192,-3.89557119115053,23.5637810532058));
#1078=CARTESIAN_POINT('',(-26.0645855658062,-3.88370355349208,23.7720122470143));
#1079=CARTESIAN_POINT('',(-25.8142662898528,-3.85823328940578,24.1779022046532));
#1080=CARTESIAN_POINT('',(-25.680577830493,-3.84463034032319,24.3755589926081));
#1081=CARTESIAN_POINT('',(-25.3971687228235,-3.81579314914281,24.7587906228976));
#1082=CARTESIAN_POINT('',(-25.247453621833,-3.8005594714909,24.9443696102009));
#1083=CARTESIAN_POINT('',(-24.9329066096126,-3.76855396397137,25.3023349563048));
#1084=CARTESIAN_POINT('',(-24.7680639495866,-3.75178104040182,25.4747117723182));
#1085=CARTESIAN_POINT('',(-24.424531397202,-3.71682622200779,25.8049015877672));
#1086=CARTESIAN_POINT('',(-24.2458418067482,-3.69864435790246,25.9627149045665));
#1087=CARTESIAN_POINT('',(-23.8758842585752,-3.66100076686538,26.2626669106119));
#1088=CARTESIAN_POINT('',(-23.6846162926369,-3.64153903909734,26.4048055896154));
#1089=CARTESIAN_POINT('',(-23.2908655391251,-3.60147446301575,26.6724037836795));
#1090=CARTESIAN_POINT('',(-23.0883829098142,-3.5808716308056,26.79786353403));
#1091=CARTESIAN_POINT('',(-22.6733930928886,-3.53864595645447,27.0313620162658));
#1092=CARTESIAN_POINT('',(-22.4608743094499,-3.51702193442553,27.1393799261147));
#1093=CARTESIAN_POINT('',(-22.0276217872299,-3.47293800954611,27.3370211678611));
#1094=CARTESIAN_POINT('',(-21.8068908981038,-3.45047839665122,27.4266508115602));
#1095=CARTESIAN_POINT('',(-21.3586570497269,-3.40487010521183,27.5869550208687));
#1096=CARTESIAN_POINT('',(-21.1311524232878,-3.38172125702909,27.6576248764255));
#1097=CARTESIAN_POINT('',(-20.6710428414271,-3.33490459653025,27.7794869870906));
#1098=CARTESIAN_POINT('',(-20.4384379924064,-3.31123679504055,27.830679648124));
#1099=CARTESIAN_POINT('',(-19.9693991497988,-3.26351157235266,27.9133020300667));
#1100=CARTESIAN_POINT('',(-19.732959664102,-3.23945359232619,27.9447002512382));
#1101=CARTESIAN_POINT('',(-19.258294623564,-3.19115589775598,27.9873917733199));
#1102=CARTESIAN_POINT('',(-19.0200690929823,-3.16691618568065,27.9986853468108));
#1103=CARTESIAN_POINT('',(-18.5435073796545,-3.11842550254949,28.0010981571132));
#1104=CARTESIAN_POINT('',(-18.3051711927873,-3.09417453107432,27.9922165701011));
#1105=CARTESIAN_POINT('',(-17.8301668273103,-3.04584230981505,27.9543561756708));
#1106=CARTESIAN_POINT('',(-17.5934981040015,-3.02176100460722,27.9253842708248));
#1107=CARTESIAN_POINT('',(-17.1229446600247,-2.97388166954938,27.8474855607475));
#1108=CARTESIAN_POINT('',(-16.8890664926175,-2.95008430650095,27.798518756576));
#1109=CARTESIAN_POINT('',(-16.4262361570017,-2.90299080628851,27.6809828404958));
#1110=CARTESIAN_POINT('',(-16.1972840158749,-2.87969467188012,27.6124136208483));
#1111=CARTESIAN_POINT('',(-15.7458818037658,-2.83376399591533,27.4561485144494));
#1112=CARTESIAN_POINT('',(-15.5234330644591,-2.8111295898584,27.3684487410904));
#1113=CARTESIAN_POINT('',(-15.0866646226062,-2.76668791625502,27.1745569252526));
#1114=CARTESIAN_POINT('',(-14.8723447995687,-2.74488063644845,27.0683651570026));
#1115=CARTESIAN_POINT('',(-14.4531224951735,-2.70222430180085,26.8381160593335));
#1116=CARTESIAN_POINT('',(-14.2482304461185,-2.68137630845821,26.7140395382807));
#1117=CARTESIAN_POINT('',(-13.8495646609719,-2.64081162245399,26.4489853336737));
#1118=CARTESIAN_POINT('',(-13.6557910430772,-2.62109494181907,26.3080074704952));
#1119=CARTESIAN_POINT('',(-13.2806196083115,-2.58292083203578,26.0100363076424));
#1120=CARTESIAN_POINT('',(-13.0992305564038,-2.56446429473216,25.8530318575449));
#1121=CARTESIAN_POINT('',(-12.7502489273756,-2.52895502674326,25.524210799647));
#1122=CARTESIAN_POINT('',(-12.582657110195,-2.51190237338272,25.3523933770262));
#1123=CARTESIAN_POINT('',(-12.422609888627,-2.49561739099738,25.173738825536));
#1124=B_SPLINE_CURVE_WITH_KNOTS('',3,(#1010,#1011,#1012,#1013,#1014,#1015,#1016,#1017,#1018,
#1019,#1020,#1021,#1022,#1023,#1024,#1025,#1026,#1027,#1028,#1029,#1030,#1031,#1032,#1033,#1034,
#1035,#1036,#1037,#1038,#1039,#1040,#1041,#1042,#1043,#1044,#1045,#1046,#1047,#1048,#1049,#1050,
#1051,#1052,#1053,#1054,#1055,#1056,#1057,#1058,#1059,#1060,#1061,#1062,#1063,#1064,#1065,#1066,
#1067,#1068,#1069,#1070,#1071,#1072,#1073,#1074,#1075,#1076,#1077,#1078,#1079,#1080,#1081,#1082,
#1083,#1084,#1085,#1086,#1087,#1088,#1089,#1090,#1091,#1092,#1093,#1094,#1095,#1096,#1097,#1098,
#1099,#1100,#1101,#1102,#1103,#1104,#1105,#1106,#1107,#1108,#1109,#1110,#1111,#1112,#1113,#1114,
#1115,#1116,#1117,#1118,#1119,#1120,#1121,#1122,#1123),.UNSPECIFIED.,.F.,.F.,(4,2,2,2,2,2,2,2,2,
2,2,2,2,2,2,2,2,2,2,2,2,2,2,2,2,2,2,2,2,2,2,2,2,2,2,2,2,2,2,2,2,2,2,2,2,2,2,2,2,2,2,2,2,2,2,2,
4),(0.,0.720982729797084,1.44192865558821,2.1623943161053,2.88285213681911,3.60347392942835,
4.32410648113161,5.04458581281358,5.76506078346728,6.48380161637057,7.2027896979,
7.92175300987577,8.64072657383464,9.35970963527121,10.0787086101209,10.7975303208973,
11.5166006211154,12.2346064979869,12.9526225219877,13.6706357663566,14.3886642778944,
15.1055304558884,15.8226446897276,16.5396221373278,17.256609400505,17.9729264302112,
18.6892590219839,19.4054308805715,20.1219072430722,20.8380805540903,21.5539492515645,
22.2699761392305,22.985987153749,23.7020452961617,24.4180934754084,25.1342749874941,
25.8502094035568,26.5666565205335,27.2830880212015,27.9995199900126,28.7159418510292,
29.4332127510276,30.1502370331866,30.867439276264,31.5846265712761,32.3029522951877,
33.0212682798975,33.7396135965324,34.4577122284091,35.1772544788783,35.8968006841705,
36.6164932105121,37.33617506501,38.056635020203,38.7771026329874,39.498074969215,
40.219086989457),.UNSPECIFIED.);
#1125=EDGE_CURVE('E225',#1007,#310,#1124,.T.);
#1126=ORIENTED_EDGE('',*,*,#1125,.T.);
#1127=ORIENTED_EDGE('',*,*,#311,.F.);
#1128=EDGE_LOOP('',(#1005,#1009,#1126,#1127));
#1129=FACE_BOUND('',#1128,.T.);
#1130=ADVANCED_FACE('F237',(#1129),#703,.T.);
#1131=CARTESIAN_POINT('',(0.,0.,32.9619260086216));
#1132=DIRECTION('',(0.,0.,1.));
#1133=DIRECTION('',(0.,-1.,0.));
#1134=AXIS2_PLACEMENT_3D('',#1131,#1132,#1133);
#1135=CYLINDRICAL_SURFACE('',#1134,6.);
#1136=CARTESIAN_POINT('',(0.,0.,20.2224488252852));
#1137=DIRECTION('',(0.,0.,1.));
#1138=DIRECTION('',(0.,-1.,0.));
#1139=AXIS2_PLACEMENT_3D('',#1136,#1137,#1138);
#1140=CIRCLE('',#1139,6.);
#1141=CARTESIAN_POINT('',(0.,-6.,20.2224488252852));
#1142=VERTEX_POINT('',#1141);
#1143=EDGE_CURVE('E420',#1142,#1142,#1140,.T.);
#1144=ORIENTED_EDGE('',*,*,#1143,.F.);
#1145=EDGE_LOOP('',(#1144));
#1146=FACE_BOUND('',#1145,.T.);
#1147=ORIENTED_EDGE('',*,*,#159,.T.);
#1148=EDGE_LOOP('',(#1147));
#1149=FACE_BOUND('',#1148,.T.);
#1150=ADVANCED_FACE('F427',(#1146,#1149),#1135,.F.);
#1151=CARTESIAN_POINT('',(6.,0.,20.2224488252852));
#1152=DIRECTION('',(0.,0.,-1.));
#1153=DIRECTION('',(0.,1.,0.));
#1154=AXIS2_PLACEMENT_3D('',#1151,#1152,#1153);
#1155=PLANE('',#1154);
#1156=CARTESIAN_POINT('',(0.,0.,20.2224488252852));
#1157=DIRECTION('',(0.,0.,1.));
#1158=DIRECTION('',(0.,-1.,0.));
#1159=AXIS2_PLACEMENT_3D('',#1156,#1157,#1158);
#1160=CIRCLE('',#1159,5.25);
#1161=CARTESIAN_POINT('',(0.,-5.25,20.2224488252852));
#1162=VERTEX_POINT('',#1161);
#1163=EDGE_CURVE('E418',#1162,#1162,#1160,.T.);
#1164=ORIENTED_EDGE('',*,*,#1163,.F.);
#1165=EDGE_LOOP('',(#1164));
#1166=FACE_BOUND('',#1165,.T.);
#1167=ORIENTED_EDGE('',*,*,#1143,.T.);
#1168=EDGE_LOOP('',(#1167));
#1169=FACE_BOUND('',#1168,.T.);
#1170=ADVANCED_FACE('F643',(#1166,#1169),#1155,.F.);
#1171=CARTESIAN_POINT('',(0.,0.,32.9619260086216));
#1172=DIRECTION('',(0.,0.,1.));
#1173=DIRECTION('',(0.,-1.,0.));
#1174=AXIS2_PLACEMENT_3D('',#1171,#1172,#1173);
#1175=CYLINDRICAL_SURFACE('',#1174,5.25);
#1176=CARTESIAN_POINT('',(0.,0.,18.));
#1177=DIRECTION('',(0.,0.,1.));
#1178=DIRECTION('',(0.,-1.,0.));
#1179=AXIS2_PLACEMENT_3D('',#1176,#1177,#1178);
#1180=CIRCLE('',#1179,5.25);
#1181=CARTESIAN_POINT('',(0.,-5.25,18.));
#1182=VERTEX_POINT('',#1181);
#1183=EDGE_CURVE('E415',#1182,#1182,#1180,.T.);
#1184=ORIENTED_EDGE('',*,*,#1183,.F.);
#1185=EDGE_LOOP('',(#1184));
#1186=FACE_BOUND('',#1185,.T.);
#1187=ORIENTED_EDGE('',*,*,#1163,.T.);
#1188=EDGE_LOOP('',(#1187));
#1189=FACE_BOUND('',#1188,.T.);
#1190=ADVANCED_FACE('F634',(#1186,#1189),#1175,.F.);
#1191=CARTESIAN_POINT('',(5.25,0.,18.));
#1192=DIRECTION('',(0.,0.,-1.));
#1193=DIRECTION('',(0.,1.,0.));
#1194=AXIS2_PLACEMENT_3D('',#1191,#1192,#1193);
#1195=PLANE('',#1194);
#1196=CARTESIAN_POINT('',(0.,0.,18.));
#1197=DIRECTION('',(0.,0.,1.));
#1198=DIRECTION('',(0.,-1.,0.));
#1199=AXIS2_PLACEMENT_3D('',#1196,#1197,#1198);
#1200=CIRCLE('',#1199,4.);
#1201=CARTESIAN_POINT('',(0.,-4.,18.));
#1202=VERTEX_POINT('',#1201);
#1203=EDGE_CURVE('E412',#1202,#1202,#1200,.T.);
#1204=ORIENTED_EDGE('',*,*,#1203,.F.);
#1205=EDGE_LOOP('',(#1204));
#1206=FACE_BOUND('',#1205,.T.);
#1207=ORIENTED_EDGE('',*,*,#1183,.T.);
#1208=EDGE_LOOP('',(#1207));
#1209=FACE_BOUND('',#1208,.T.);
#1210=ADVANCED_FACE('F625',(#1206,#1209),#1195,.F.);
#1211=CARTESIAN_POINT('',(0.,0.,32.9619260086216));
#1212=DIRECTION('',(0.,0.,1.));
#1213=DIRECTION('',(0.,-1.,0.));
#1214=AXIS2_PLACEMENT_3D('',#1211,#1212,#1213);
#1215=CYLINDRICAL_SURFACE('',#1214,4.);
#1216=ORIENTED_EDGE('',*,*,#377,.F.);
#1217=EDGE_LOOP('',(#1216));
#1218=FACE_BOUND('',#1217,.T.);
#1219=ORIENTED_EDGE('',*,*,#1203,.T.);
#1220=EDGE_LOOP('',(#1219));
#1221=FACE_BOUND('',#1220,.T.);
#1222=ADVANCED_FACE('F618',(#1218,#1221),#1215,.F.);
#1223=CARTESIAN_POINT('',(-5.40709709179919,-6.07628287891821,7.74949494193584));
#1224=CARTESIAN_POINT('',(-5.52832692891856,-5.89355006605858,7.74300062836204));
#1225=CARTESIAN_POINT('',(-5.65714597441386,-5.71578413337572,7.73856775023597));
#1226=CARTESIAN_POINT('',(-5.92896359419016,-5.37140070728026,7.73381126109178));
#1227=CARTESIAN_POINT('',(-6.07196145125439,-5.20478265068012,7.73348744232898));
#1228=CARTESIAN_POINT('',(-6.37106927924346,-4.88397779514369,7.73693388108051));
#1229=CARTESIAN_POINT('',(-6.52717210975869,-4.72978431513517,7.74070192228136));
#1230=CARTESIAN_POINT('',(-6.85142573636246,-4.43480905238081,7.75237463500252));
#1231=CARTESIAN_POINT('',(-7.01957640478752,-4.29402712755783,7.76027926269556));
#1232=CARTESIAN_POINT('',(-7.3673220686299,-4.02637592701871,7.7803347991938));
#1233=CARTESIAN_POINT('',(-7.5469554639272,-3.89955765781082,7.79250063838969));
#1234=CARTESIAN_POINT('',(-7.9158064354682,-3.66127029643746,7.82115395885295));
#1235=CARTESIAN_POINT('',(-8.10502419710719,-3.54980150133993,7.83764152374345));
#1236=CARTESIAN_POINT('',(-8.49153693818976,-3.34300255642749,7.87498590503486));
#1237=CARTESIAN_POINT('',(-8.68882754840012,-3.24766381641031,7.8958403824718));
#1238=CARTESIAN_POINT('',(-9.09012356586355,-3.0736420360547,7.9419380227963));
#1239=CARTESIAN_POINT('',(-9.29412893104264,-2.99495889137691,7.96718115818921));
#1240=CARTESIAN_POINT('',(-9.70741231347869,-2.85467316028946,8.02202231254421));
#1241=CARTESIAN_POINT('',(-9.91669157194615,-2.79307463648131,8.05162136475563));
#1242=CARTESIAN_POINT('',(-10.339055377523,-2.68725515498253,8.11508504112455));
#1243=CARTESIAN_POINT('',(-10.5521414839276,-2.64304149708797,8.14895144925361));
#1244=CARTESIAN_POINT('',(-10.9807065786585,-2.57214841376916,8.22081700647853));
#1245=CARTESIAN_POINT('',(-11.1961874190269,-2.54548368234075,8.25881958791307));
#1246=CARTESIAN_POINT('',(-11.6277899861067,-2.50976534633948,8.33871508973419));
#1247=CARTESIAN_POINT('',(-11.8439114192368,-2.50070464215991,8.38060643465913));
#1248=CARTESIAN_POINT('',(-12.2800333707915,-2.50004860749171,8.4689808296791));
#1249=CARTESIAN_POINT('',(-12.5000184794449,-2.50882934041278,8.5155426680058));
#1250=CARTESIAN_POINT('',(-12.9377641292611,-2.54436339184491,8.61219040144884));
#1251=CARTESIAN_POINT('',(-13.1555244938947,-2.57111812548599,8.66227657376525));
#1252=CARTESIAN_POINT('',(-13.5871820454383,-2.64220826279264,8.76559927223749));
#1253=CARTESIAN_POINT('',(-13.8010824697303,-2.68652814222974,8.81883298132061));
#1254=CARTESIAN_POINT('',(-14.223841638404,-2.79225594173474,8.9281302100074));
#1255=CARTESIAN_POINT('',(-14.4327011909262,-2.85366110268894,8.98419327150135));
#1256=CARTESIAN_POINT('',(-14.6383874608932,-2.9233697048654,9.0414994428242));
#1257=B_SPLINE_CURVE_WITH_KNOTS('',3,(#1223,#1224,#1225,#1226,#1227,#1228,#1229,#1230,#1231,
#1232,#1233,#1234,#1235,#1236,#1237,#1238,#1239,#1240,#1241,#1242,#1243,#1244,#1245,#1246,#1247,
#1248,#1249,#1250,#1251,#1252,#1253,#1254,#1255,#1256),.UNSPECIFIED.,.F.,.F.,(4,2,2,2,2,2,2,2,2,
2,2,2,2,2,2,2,4),(0.,0.657956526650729,1.3158797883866,1.97344687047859,2.63100698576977,
3.29089448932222,3.95079476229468,4.61034248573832,5.2698860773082,5.9295863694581,
6.58956337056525,7.25009228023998,7.91035474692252,8.58467859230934,9.25905553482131,
9.93283778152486,10.6065112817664),.UNSPECIFIED.);
#1258=CARTESIAN_POINT('',(-12.9964083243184,-2.55400201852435,8.6262188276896));
#1259=VERTEX_POINT('',#1258);
#1260=EDGE_CURVE('E451',#1259,#514,#1257,.F.);
#1261=ORIENTED_EDGE('',*,*,#1260,.F.);
#1262=CARTESIAN_POINT('',(-12.9962083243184,-2.55398166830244,8.6261732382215));
#1263=CARTESIAN_POINT('',(-13.7932617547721,-2.6350827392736,8.80783637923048));
#1264=CARTESIAN_POINT('',(-14.5856701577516,-2.71571117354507,9.01008449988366));
#1265=CARTESIAN_POINT('',(-16.1570654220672,-2.87560238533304,9.45457114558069));
#1266=CARTESIAN_POINT('',(-16.9360820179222,-2.95486818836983,9.6967034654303));
#1267=CARTESIAN_POINT('',(-18.4807629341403,-3.11204118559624,10.220738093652));
#1268=CARTESIAN_POINT('',(-19.2464272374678,-3.18994837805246,10.5026404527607));
#1269=CARTESIAN_POINT('',(-20.7643941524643,-3.34440319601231,11.1062490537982));
#1270=CARTESIAN_POINT('',(-21.5166563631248,-3.4209467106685,11.4280579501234));
#1271=CARTESIAN_POINT('',(-22.2601932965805,-3.4966024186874,11.7690934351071));
#1272=B_SPLINE_CURVE_WITH_KNOTS('',3,(#1262,#1263,#1264,#1265,#1266,#1267,#1268,#1269,#1270,
#1271),.UNSPECIFIED.,.F.,.F.,(4,2,2,2,4),(0.,2.46424751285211,4.92203617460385,7.37982797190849,
9.84407863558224),.UNSPECIFIED.);
#1273=EDGE_CURVE('E485',#1259,#1007,#1272,.T.);
#1274=ORIENTED_EDGE('',*,*,#1273,.T.);
#1275=ORIENTED_EDGE('',*,*,#1008,.F.);
#1276=CARTESIAN_POINT('',(-13.1526156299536,2.57444288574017,8.66230481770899));
#1277=CARTESIAN_POINT('',(-13.9359553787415,2.65389517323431,8.84362255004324));
#1278=CARTESIAN_POINT('',(-14.7147354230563,2.73288498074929,9.04483639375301));
#1279=CARTESIAN_POINT('',(-16.2592477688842,2.88954119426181,9.48592426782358));
#1280=CARTESIAN_POINT('',(-17.0250081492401,2.96721044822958,9.72569896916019));
#1281=CARTESIAN_POINT('',(-18.5435464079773,3.12123217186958,10.2437024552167));
#1282=CARTESIAN_POINT('',(-19.2963242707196,3.19758463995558,10.5219312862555));
#1283=CARTESIAN_POINT('',(-20.7888885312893,3.34897188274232,11.1168748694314));
#1284=CARTESIAN_POINT('',(-21.5286370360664,3.4240028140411,11.4336856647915));
#1285=CARTESIAN_POINT('',(-22.2599457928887,3.49817772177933,11.7690934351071));
#1286=B_SPLINE_CURVE_WITH_KNOTS('',3,(#1276,#1277,#1278,#1279,#1280,#1281,#1282,#1283,#1284,
#1285),.UNSPECIFIED.,.F.,.F.,(4,2,2,2,4),(0.,2.42364073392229,4.84113555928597,7.258633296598,
9.68227695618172),.UNSPECIFIED.);
#1287=CARTESIAN_POINT('',(-13.1528156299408,2.57446317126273,8.66235111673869));
#1288=VERTEX_POINT('',#1287);
#1289=EDGE_CURVE('E188',#1288,#1003,#1286,.T.);
#1290=ORIENTED_EDGE('',*,*,#1289,.F.);
#1291=CARTESIAN_POINT('',(-5.406831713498,6.0762183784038,7.7494688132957));
#1292=CARTESIAN_POINT('',(-5.52812198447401,5.89347890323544,7.74297839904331));
#1293=CARTESIAN_POINT('',(-5.65700170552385,5.71570882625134,7.73854990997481));
#1294=CARTESIAN_POINT('',(-5.92894070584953,5.37132213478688,7.73380323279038));
#1295=CARTESIAN_POINT('',(-6.07199926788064,5.20470495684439,7.73348483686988));
#1296=CARTESIAN_POINT('',(-6.37122802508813,4.88390689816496,7.73694320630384));
#1297=CARTESIAN_POINT('',(-6.52739107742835,4.72971933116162,7.74071775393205));
#1298=CARTESIAN_POINT('',(-6.85176427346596,4.43476082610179,7.75240465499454));
#1299=CARTESIAN_POINT('',(-7.01997428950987,4.29398974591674,7.76031696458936));
#1300=CARTESIAN_POINT('',(-7.36783783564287,4.02636487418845,7.78038916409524));
#1301=CARTESIAN_POINT('',(-7.54752977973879,3.89956213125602,7.79256399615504));
#1302=CARTESIAN_POINT('',(-7.91649610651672,3.66131057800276,7.82123662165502));
#1303=CARTESIAN_POINT('',(-8.10577067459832,3.54986206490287,7.837734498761));
#1304=CARTESIAN_POINT('',(-8.49239482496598,3.34310822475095,7.87510081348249));
#1305=CARTESIAN_POINT('',(-8.68974003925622,3.24779430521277,7.89596691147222));
#1306=CARTESIAN_POINT('',(-9.09114269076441,3.07382646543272,7.94208905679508));
#1307=CARTESIAN_POINT('',(-9.29520008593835,2.99517244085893,7.96734507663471));
#1308=CARTESIAN_POINT('',(-9.7085848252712,2.85494889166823,8.02221321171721));
#1309=CARTESIAN_POINT('',(-9.91791341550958,2.79338344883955,8.05182636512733));
#1310=CARTESIAN_POINT('',(-10.3403726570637,2.68763386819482,8.11531933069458));
#1311=CARTESIAN_POINT('',(-10.5535048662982,2.64345703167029,8.14920092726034));
#1312=CARTESIAN_POINT('',(-10.982158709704,2.5726409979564,8.22109783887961));
#1313=CARTESIAN_POINT('',(-11.1976821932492,2.54601649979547,8.25911658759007));
#1314=CARTESIAN_POINT('',(-11.6293662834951,2.51038163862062,8.3390452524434));
#1315=CARTESIAN_POINT('',(-11.8455265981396,2.50136417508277,8.38095359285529));
#1316=CARTESIAN_POINT('',(-12.2817256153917,2.50079822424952,8.46936354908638));
#1317=CARTESIAN_POINT('',(-12.5017488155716,2.50962605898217,8.51594401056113));
#1318=CARTESIAN_POINT('',(-12.9395663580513,2.54525709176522,8.61262967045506));
#1319=CARTESIAN_POINT('',(-13.1573605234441,2.57206170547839,8.66273514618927));
#1320=CARTESIAN_POINT('',(-13.589081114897,2.64325392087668,8.76609695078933));
#1321=CARTESIAN_POINT('',(-13.8030107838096,2.68762598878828,8.81935046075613));
#1322=CARTESIAN_POINT('',(-14.225823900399,2.79346013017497,8.92868768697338));
#1323=CARTESIAN_POINT('',(-14.4347081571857,2.85491944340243,8.98477094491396));
#1324=CARTESIAN_POINT('',(-14.640416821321,2.92468299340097,9.0420974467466));
#1325=B_SPLINE_CURVE_WITH_KNOTS('',3,(#1291,#1292,#1293,#1294,#1295,#1296,#1297,#1298,#1299,
#1300,#1301,#1302,#1303,#1304,#1305,#1306,#1307,#1308,#1309,#1310,#1311,#1312,#1313,#1314,#1315,
#1316,#1317,#1318,#1319,#1320,#1321,#1322,#1323,#1324),.UNSPECIFIED.,.F.,.F.,(4,2,2,2,2,2,2,2,2,
2,2,2,2,2,2,2,4),(0.,0.658072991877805,1.31611271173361,1.97379605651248,2.63147243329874,
3.2914777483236,3.95149583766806,4.61116132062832,5.27082267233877,5.93064145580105,
6.59073699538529,7.2513846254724,7.91176577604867,8.58621828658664,9.26072391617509,
9.93463445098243,10.6084361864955),.UNSPECIFIED.);
#1326=EDGE_CURVE('E164',#518,#1288,#1325,.T.);
#1327=ORIENTED_EDGE('',*,*,#1326,.F.);
#1328=ORIENTED_EDGE('',*,*,#519,.T.);
#1329=EDGE_LOOP('',(#1261,#1274,#1275,#1290,#1327,#1328));
#1330=FACE_BOUND('',#1329,.T.);
#1331=ADVANCED_FACE('F202',(#1330),#579,.T.);
#1332=CARTESIAN_POINT('',(-13.1528156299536,2.57446317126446,-7.0380739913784));
#1333=DIRECTION('',(0.100909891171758,0.994895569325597,0.));
#1334=DIRECTION('',(-0.994895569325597,0.100909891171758,0.));
#1335=AXIS2_PLACEMENT_3D('',#1332,#1333,#1334);
#1336=PLANE('',#1335);
#1337=CARTESIAN_POINT('',(-18.9983287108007,3.16735965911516,19.5));
#1338=DIRECTION('',(0.100909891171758,0.994895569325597,0.));
#1339=DIRECTION('',(-0.994895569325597,0.100909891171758,0.));
#1340=AXIS2_PLACEMENT_3D('',#1337,#1338,#1339);
#1341=CIRCLE('',#1340,6.01077275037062);
#1342=CARTESIAN_POINT('',(-13.1528156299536,2.57446317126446,18.2319938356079));
#1343=VERTEX_POINT('',#1342);
#1344=CARTESIAN_POINT('',(-13.1528156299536,2.57446317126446,20.768006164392));
#1345=VERTEX_POINT('',#1344);
#1346=EDGE_CURVE('E34',#1343,#1345,#1341,.T.);
#1347=ORIENTED_EDGE('',*,*,#1346,.F.);
#1348=DIRECTION('',(0.,0.,1.));
#1349=VECTOR('',#1348,1.);
#1350=CARTESIAN_POINT('',(-13.1528156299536,2.57446317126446,-7.0380739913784));
#1351=LINE('',#1350,#1349);
#1352=EDGE_CURVE('E156',#1288,#1343,#1351,.T.);
#1353=ORIENTED_EDGE('',*,*,#1352,.F.);
#1354=ORIENTED_EDGE('',*,*,#1289,.T.);
#1355=ORIENTED_EDGE('',*,*,#1004,.T.);
#1356=ORIENTED_EDGE('',*,*,#307,.F.);
#1357=EDGE_CURVE('E158',#1345,#295,#1351,.T.);
#1358=ORIENTED_EDGE('',*,*,#1357,.F.);
#1359=EDGE_LOOP('',(#1347,#1353,#1354,#1355,#1356,#1358));
#1360=FACE_BOUND('',#1359,.T.);
#1361=ADVANCED_FACE('F154',(#1360),#1336,.T.);
#1362=CARTESIAN_POINT('',(-12.0717114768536,10.5010774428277,-7.0380739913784));
#1363=DIRECTION('',(0.,0.,1.));
#1364=DIRECTION('',(0.,-1.,0.));
#1365=AXIS2_PLACEMENT_3D('',#1362,#1363,#1364);
#1366=CYLINDRICAL_SURFACE('',#1365,8.);
#1367=CARTESIAN_POINT('',(-13.1530156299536,2.57449045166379,20.769033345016));
#1368=CARTESIAN_POINT('',(-13.1325676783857,2.57170354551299,20.6640900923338));
#1369=CARTESIAN_POINT('',(-13.1144634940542,2.56931150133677,20.5586857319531));
#1370=CARTESIAN_POINT('',(-13.0832029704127,2.56526374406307,20.3471123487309));
#1371=CARTESIAN_POINT('',(-13.0700476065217,2.56360817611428,20.240943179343));
#1372=CARTESIAN_POINT('',(-13.038618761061,2.55969394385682,19.9237331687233));
#1373=CARTESIAN_POINT('',(-13.027960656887,2.55843383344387,19.7118665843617));
#1374=CARTESIAN_POINT('',(-13.027960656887,2.55843383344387,19.2881334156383));
#1375=CARTESIAN_POINT('',(-13.038618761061,2.55969394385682,19.0762668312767));
#1376=CARTESIAN_POINT('',(-13.0700476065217,2.56360817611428,18.759056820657));
#1377=CARTESIAN_POINT('',(-13.0832029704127,2.56526374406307,18.6528876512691));
#1378=CARTESIAN_POINT('',(-13.1144634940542,2.56931150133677,18.4413142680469));
#1379=CARTESIAN_POINT('',(-13.1325676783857,2.57170354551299,18.3359099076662));
#1380=CARTESIAN_POINT('',(-13.1530156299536,2.57449045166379,18.230966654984));
#1381=B_SPLINE_CURVE_WITH_KNOTS('',3,(#1367,#1368,#1369,#1370,#1371,#1372,#1373,#1374,#1375,
#1376,#1377,#1378,#1379,#1380),.UNSPECIFIED.,.F.,.F.,(4,2,2,2,2,2,4),(0.,0.320814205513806,
0.641691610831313,1.27697796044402,1.91226431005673,2.23314171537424,2.55395592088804),.UNSPECIFIED.);
#1382=EDGE_CURVE('E9',#1345,#1343,#1381,.T.);
#1383=ORIENTED_EDGE('',*,*,#1382,.F.);
#1384=ORIENTED_EDGE('',*,*,#1357,.T.);
#1385=ORIENTED_EDGE('',*,*,#296,.F.);
#1386=ORIENTED_EDGE('',*,*,#424,.F.);
#1387=ORIENTED_EDGE('',*,*,#408,.F.);
#1388=ORIENTED_EDGE('',*,*,#443,.T.);
#1389=ORIENTED_EDGE('',*,*,#570,.F.);
#1390=ORIENTED_EDGE('',*,*,#1326,.T.);
#1391=ORIENTED_EDGE('',*,*,#1352,.T.);
#1392=EDGE_LOOP('',(#1383,#1384,#1385,#1386,#1387,#1388,#1389,#1390,#1391));
#1393=FACE_BOUND('',#1392,.T.);
#1394=ADVANCED_FACE('F162',(#1393),#1366,.F.);
#1395=CARTESIAN_POINT('',(13.1528156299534,2.57446317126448,-7.0380739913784));
#1396=DIRECTION('',(0.100909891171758,-0.994895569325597,0.));
#1397=DIRECTION('',(0.994895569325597,0.100909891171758,0.));
#1398=AXIS2_PLACEMENT_3D('',#1395,#1396,#1397);
#1399=PLANE('',#1398);
#1400=DIRECTION('',(0.,0.,1.));
#1401=VECTOR('',#1400,1.);
#1402=CARTESIAN_POINT('',(13.1528156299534,2.57446317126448,-7.0380739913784));
#1403=LINE('',#1402,#1401);
#1404=CARTESIAN_POINT('',(13.1528156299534,2.57446317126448,18.2319938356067));
#1405=VERTEX_POINT('',#1404);
#1406=EDGE_CURVE('E185',#617,#1405,#1403,.T.);
#1407=ORIENTED_EDGE('',*,*,#1406,.T.);
#1408=CARTESIAN_POINT('',(18.9983287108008,3.1673596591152,19.5));
#1409=DIRECTION('',(0.100909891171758,-0.994895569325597,0.));
#1410=DIRECTION('',(0.994895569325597,0.100909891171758,0.));
#1411=AXIS2_PLACEMENT_3D('',#1408,#1409,#1410);
#1412=CIRCLE('',#1411,6.01077275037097);
#1413=CARTESIAN_POINT('',(13.1528156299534,2.57446317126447,20.7680061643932));
#1414=VERTEX_POINT('',#1413);
#1415=EDGE_CURVE('E41',#1405,#1414,#1412,.T.);
#1416=ORIENTED_EDGE('',*,*,#1415,.T.);
#1417=EDGE_CURVE('E184',#1414,#224,#1403,.T.);
#1418=ORIENTED_EDGE('',*,*,#1417,.T.);
#1419=ORIENTED_EDGE('',*,*,#225,.T.);
#1420=ORIENTED_EDGE('',*,*,#909,.F.);
#1421=ORIENTED_EDGE('',*,*,#633,.F.);
#1422=EDGE_LOOP('',(#1407,#1416,#1418,#1419,#1420,#1421));
#1423=FACE_BOUND('',#1422,.T.);
#1424=ADVANCED_FACE('F240',(#1423),#1399,.F.);
#1425=CARTESIAN_POINT('',(12.0717114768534,10.5010774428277,-7.0380739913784));
#1426=DIRECTION('',(0.,0.,1.));
#1427=DIRECTION('',(0.,-1.,0.));
#1428=AXIS2_PLACEMENT_3D('',#1425,#1426,#1427);
#1429=CYLINDRICAL_SURFACE('',#1428,8.);
#1430=ORIENTED_EDGE('',*,*,#1417,.F.);
#1431=CARTESIAN_POINT('',(13.1530156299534,2.57449045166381,20.7690333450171));
#1432=CARTESIAN_POINT('',(13.1325676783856,2.57170354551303,20.6640900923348));
#1433=CARTESIAN_POINT('',(13.1144634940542,2.56931150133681,20.558685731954));
#1434=CARTESIAN_POINT('',(13.0832029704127,2.56526374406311,20.3471123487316));
#1435=CARTESIAN_POINT('',(13.0700476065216,2.56360817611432,20.2409431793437));
#1436=CARTESIAN_POINT('',(13.0386187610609,2.55969394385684,19.9237331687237));
#1437=CARTESIAN_POINT('',(13.0279606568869,2.5584338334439,19.7118665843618));
#1438=CARTESIAN_POINT('',(13.0279606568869,2.5584338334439,19.2881334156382));
#1439=CARTESIAN_POINT('',(13.0386187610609,2.55969394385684,19.0762668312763));
#1440=CARTESIAN_POINT('',(13.0700476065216,2.56360817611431,18.7590568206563));
#1441=CARTESIAN_POINT('',(13.0832029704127,2.56526374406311,18.6528876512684));
#1442=CARTESIAN_POINT('',(13.1144634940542,2.56931150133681,18.441314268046));
#1443=CARTESIAN_POINT('',(13.1325676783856,2.57170354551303,18.3359099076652));
#1444=CARTESIAN_POINT('',(13.1530156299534,2.5744904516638,18.2309666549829));
#1445=B_SPLINE_CURVE_WITH_KNOTS('',3,(#1431,#1432,#1433,#1434,#1435,#1436,#1437,#1438,#1439,
#1440,#1441,#1442,#1443,#1444),.UNSPECIFIED.,.F.,.F.,(4,2,2,2,2,2,4),(0.,0.320814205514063,
0.641691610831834,1.27697796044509,1.91226431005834,2.23314171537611,2.55395592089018),.UNSPECIFIED.);
#1446=EDGE_CURVE('E29',#1414,#1405,#1445,.T.);
#1447=ORIENTED_EDGE('',*,*,#1446,.T.);
#1448=ORIENTED_EDGE('',*,*,#1406,.F.);
#1449=ORIENTED_EDGE('',*,*,#618,.F.);
#1450=ORIENTED_EDGE('',*,*,#94,.T.);
#1451=ORIENTED_EDGE('',*,*,#450,.F.);
#1452=ORIENTED_EDGE('',*,*,#390,.T.);
#1453=ORIENTED_EDGE('',*,*,#431,.T.);
#1454=ORIENTED_EDGE('',*,*,#256,.T.);
#1455=EDGE_LOOP('',(#1430,#1447,#1448,#1449,#1450,#1451,#1452,#1453,#1454));
#1456=FACE_BOUND('',#1455,.T.);
#1457=ADVANCED_FACE('F262',(#1456),#1429,.F.);
#1458=CARTESIAN_POINT('',(12.9964083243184,-2.55400201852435,-7.0380739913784));
#1459=DIRECTION('',(-0.101228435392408,-0.994863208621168,0.));
#1460=DIRECTION('',(0.994863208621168,-0.101228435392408,0.));
#1461=AXIS2_PLACEMENT_3D('',#1458,#1459,#1460);
#1462=PLANE('',#1461);
#1463=CARTESIAN_POINT('',(19.0039855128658,-3.16527966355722,19.5));
#1464=DIRECTION('',(-0.101228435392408,-0.994863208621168,0.));
#1465=DIRECTION('',(0.994863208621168,-0.101228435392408,0.));
#1466=AXIS2_PLACEMENT_3D('',#1463,#1464,#1465);
#1467=CIRCLE('',#1466,6.00333352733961);
#1468=CARTESIAN_POINT('',(24.9764811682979,-3.7729877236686,19.5));
#1469=VERTEX_POINT('',#1468);
#1470=EDGE_CURVE('E521',#1469,#1469,#1467,.T.);
#1471=ORIENTED_EDGE('',*,*,#1470,.F.);
#1472=EDGE_LOOP('',(#1471));
#1473=FACE_BOUND('',#1472,.T.);
#1474=ORIENTED_EDGE('',*,*,#205,.F.);
#1475=DIRECTION('',(0.,0.,1.));
#1476=VECTOR('',#1475,1.);
#1477=CARTESIAN_POINT('',(12.9964083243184,-2.55400201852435,-7.0380739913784));
#1478=LINE('',#1477,#1476);
#1479=EDGE_CURVE('E181',#656,#191,#1478,.T.);
#1480=ORIENTED_EDGE('',*,*,#1479,.F.);
#1481=ORIENTED_EDGE('',*,*,#657,.T.);
#1482=ORIENTED_EDGE('',*,*,#819,.T.);
#1483=EDGE_LOOP('',(#1474,#1480,#1481,#1482));
#1484=FACE_BOUND('',#1483,.T.);
#1485=ADVANCED_FACE('F258',(#1473,#1484),#1462,.T.);
#1486=CARTESIAN_POINT('',(-12.9964083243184,-2.55400201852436,-7.0380739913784));
#1487=DIRECTION('',(-0.101228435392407,0.994863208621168,0.));
#1488=DIRECTION('',(-0.994863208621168,-0.101228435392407,0.));
#1489=AXIS2_PLACEMENT_3D('',#1486,#1487,#1488);
#1490=PLANE('',#1489);
#1491=CARTESIAN_POINT('',(-19.0039855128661,-3.16527966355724,19.5));
#1492=DIRECTION('',(-0.101228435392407,0.994863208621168,0.));
#1493=DIRECTION('',(-0.994863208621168,-0.101228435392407,0.));
#1494=AXIS2_PLACEMENT_3D('',#1491,#1492,#1493);
#1495=CIRCLE('',#1494,6.00333352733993);
#1496=CARTESIAN_POINT('',(-24.9764811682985,-3.77298772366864,19.5));
#1497=VERTEX_POINT('',#1496);
#1498=EDGE_CURVE('E159',#1497,#1497,#1495,.T.);
#1499=ORIENTED_EDGE('',*,*,#1498,.T.);
#1500=EDGE_LOOP('',(#1499));
#1501=FACE_BOUND('',#1500,.T.);
#1502=DIRECTION('',(0.,0.,1.));
#1503=VECTOR('',#1502,1.);
#1504=CARTESIAN_POINT('',(-12.9964083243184,-2.55400201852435,-7.0380739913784));
#1505=LINE('',#1504,#1503);
#1506=EDGE_CURVE('E165',#1259,#321,#1505,.T.);
#1507=ORIENTED_EDGE('',*,*,#1506,.T.);
#1508=ORIENTED_EDGE('',*,*,#322,.T.);
#1509=ORIENTED_EDGE('',*,*,#1125,.F.);
#1510=ORIENTED_EDGE('',*,*,#1273,.F.);
#1511=EDGE_LOOP('',(#1507,#1508,#1509,#1510));
#1512=FACE_BOUND('',#1511,.T.);
#1513=ADVANCED_FACE('F211',(#1501,#1512),#1490,.F.);
#1514=CARTESIAN_POINT('',(12.0717114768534,-10.498922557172,-7.0380739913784));
#1515=DIRECTION('',(0.,0.,1.));
#1516=DIRECTION('',(0.,-1.,0.));
#1517=AXIS2_PLACEMENT_3D('',#1514,#1515,#1516);
#1518=CYLINDRICAL_SURFACE('',#1517,7.99855153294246);
#1519=ORIENTED_EDGE('',*,*,#1479,.T.);
#1520=ORIENTED_EDGE('',*,*,#194,.T.);
#1521=ORIENTED_EDGE('',*,*,#454,.F.);
#1522=ORIENTED_EDGE('',*,*,#142,.T.);
#1523=ORIENTED_EDGE('',*,*,#694,.F.);
#1524=EDGE_LOOP('',(#1519,#1520,#1521,#1522,#1523));
#1525=FACE_BOUND('',#1524,.T.);
#1526=ADVANCED_FACE('F264',(#1525),#1518,.F.);
#1527=CARTESIAN_POINT('',(-12.0717114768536,-10.498922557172,-7.0380739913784));
#1528=DIRECTION('',(0.,0.,1.));
#1529=DIRECTION('',(0.,-1.,0.));
#1530=AXIS2_PLACEMENT_3D('',#1527,#1528,#1529);
#1531=CYLINDRICAL_SURFACE('',#1530,7.99855153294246);
#1532=ORIENTED_EDGE('',*,*,#353,.F.);
#1533=ORIENTED_EDGE('',*,*,#1506,.F.);
#1534=ORIENTED_EDGE('',*,*,#1260,.T.);
#1535=ORIENTED_EDGE('',*,*,#515,.F.);
#1536=ORIENTED_EDGE('',*,*,#463,.T.);
#1537=EDGE_LOOP('',(#1532,#1533,#1534,#1535,#1536));
#1538=FACE_BOUND('',#1537,.T.);
#1539=ADVANCED_FACE('F465',(#1538),#1531,.F.);
#1540=CARTESIAN_POINT('',(17.2910340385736,-20.,19.5));
#1541=DIRECTION('',(0.,-1.,0.));
#1542=DIRECTION('',(1.,0.,0.));
#1543=AXIS2_PLACEMENT_3D('',#1540,#1541,#1542);
#1544=SPHERICAL_SURFACE('',#1543,17.955);
#1545=CARTESIAN_POINT('',(17.2910340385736,-20.,19.5));
#1546=DIRECTION('',(-0.101228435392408,-0.994863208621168,0.));
#1547=DIRECTION('',(0.994863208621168,-0.101228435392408,0.));
#1548=AXIS2_PLACEMENT_3D('',#1545,#1546,#1547);
#1549=SPHERICAL_SURFACE('',#1548,17.955);
#1550=ORIENTED_EDGE('',*,*,#1470,.T.);
#1551=EDGE_LOOP('',(#1550));
#1552=FACE_BOUND('',#1551,.T.);
#1553=ADVANCED_FACE('F360',(#1552),#1549,.F.);
#1554=CARTESIAN_POINT('',(17.2910340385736,20.,19.5));
#1555=DIRECTION('',(0.,1.,0.));
#1556=DIRECTION('',(1.,0.,0.));
#1557=AXIS2_PLACEMENT_3D('',#1554,#1555,#1556);
#1558=SPHERICAL_SURFACE('',#1557,17.955);
#1559=ORIENTED_EDGE('',*,*,#1446,.F.);
#1560=ORIENTED_EDGE('',*,*,#1415,.F.);
#1561=EDGE_LOOP('',(#1559,#1560));
#1562=FACE_BOUND('',#1561,.T.);
#1563=ADVANCED_FACE('F477',(#1562),#1558,.F.);
#1564=CARTESIAN_POINT('',(-17.2910340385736,-20.,19.5));
#1565=DIRECTION('',(0.,-1.,0.));
#1566=DIRECTION('',(-1.,0.,0.));
#1567=AXIS2_PLACEMENT_3D('',#1564,#1565,#1566);
#1568=SPHERICAL_SURFACE('',#1567,17.955);
#1569=CARTESIAN_POINT('',(-17.2910340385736,-20.,19.5));
#1570=DIRECTION('',(-0.101228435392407,0.994863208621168,0.));
#1571=DIRECTION('',(-0.994863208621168,-0.101228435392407,0.));
#1572=AXIS2_PLACEMENT_3D('',#1569,#1570,#1571);
#1573=SPHERICAL_SURFACE('',#1572,17.955);
#1574=ORIENTED_EDGE('',*,*,#1498,.F.);
#1575=EDGE_LOOP('',(#1574));
#1576=FACE_BOUND('',#1575,.T.);
#1577=ADVANCED_FACE('F537',(#1576),#1573,.F.);
#1578=CARTESIAN_POINT('',(-17.2910340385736,20.,19.5));
#1579=DIRECTION('',(0.,1.,0.));
#1580=DIRECTION('',(-1.,0.,0.));
#1581=AXIS2_PLACEMENT_3D('',#1578,#1579,#1580);
#1582=SPHERICAL_SURFACE('',#1581,17.955);
#1583=ORIENTED_EDGE('',*,*,#1346,.T.);
#1584=ORIENTED_EDGE('',*,*,#1382,.T.);
#1585=EDGE_LOOP('',(#1583,#1584));
#1586=FACE_BOUND('',#1585,.T.);
#1587=ADVANCED_FACE('F148',(#1586),#1582,.F.);
#1588=CLOSED_SHELL('',(#146,#364,#414,#436,#473,#574,#698,#914,#1130,#1150,#1170,#1190,#1210,
#1222,#1331,#1361,#1394,#1424,#1457,#1485,#1513,#1526,#1539,#1553,#1563,#1577,#1587));
#1589=MANIFOLD_SOLID_BREP('B1',#1588);
#1590=ADVANCED_BREP_SHAPE_REPRESENTATION('',(#18,#1589),#14);
#1591=SHAPE_DEFINITION_REPRESENTATION(#9,#1590);
ENDSEC;
END-ISO-10303-21;
